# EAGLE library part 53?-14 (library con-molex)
CONNECTOR wire to board 1.25 mm (.049 inch) pitch header

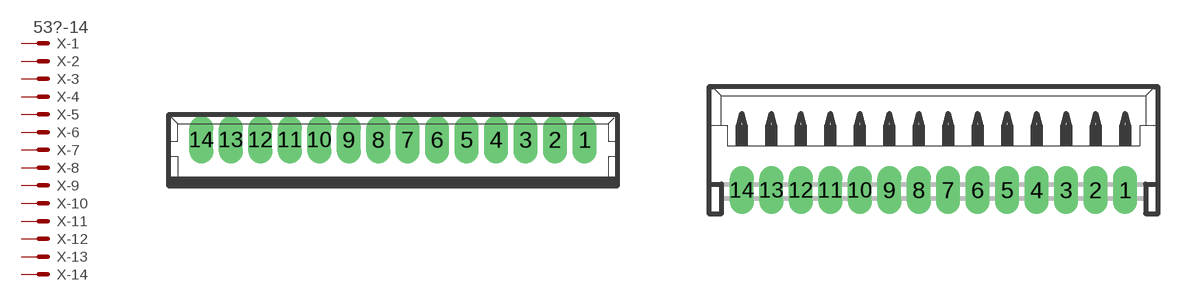
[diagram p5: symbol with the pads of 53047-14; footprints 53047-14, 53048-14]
Designator prefix X; gates -1=MV -2=M -3=M -4=M -5=M -6=M -7=M -8=M -9=M -10=M -11=M -12=M -13=M -14=M

## 53047-14 (MPN: 53047-1410; OC_FARNELL: 9732900; OC_NEWARK: 98K9830)  [53047-14]
1  -1:S  pas
2  -2:S  pas
3  -3:S  pas
4  -4:S  pas
5  -5:S  pas
6  -6:S  pas
7  -7:S  pas
8  -8:S  pas
9  -9:S  pas
10  -10:S  pas
11  -11:S  pas
12  -12:S  pas
13  -13:S  pas
14  -14:S  pas

## 53048-14 (MPN: 53048-1410; OC_FARNELL: 1012240; OC_NEWARK: 98K9839)  [53048-14]
Pads as for 53047-14

## 53261-14 (OC_FARNELL: 1125364; OC_NEWARK: unknown)  [53261-14]
Pads as for 53047-14

## 53398-14 (OC_FARNELL: 9786384; OC_NEWARK: unknown)  [53398-14]
Pads as for 53047-14

## Footprint 53047-14 (pad centres in mm)
CONNECTOR wire to board 1.25 mm (.049 inch) pitch header straight Sourcxe: http://www.molex.com/pdm_docs/sd/530470210_sd.pdf
drill 0.5 pad 0.698 long: 1 8.125,0.45; 2 6.875,0.45; 3 5.625,0.45; 4 4.375,0.45; 5 3.125,0.45; 6 1.875,0.45; 7 0.625,0.45; 8 -0.625,0.45; 9 -1.875,0.45; 10 -3.125,0.45; 11 -4.375,0.45; 12 -5.625,0.45; 13 -6.875,0.45; 14 -8.125,0.45

## Footprint 53048-14 (pad centres in mm)
CONNECTOR wire to board 1.25 mm (.049 inch) pitch header right angle
drill 0.5 pad 0.698 long: 1 8.125,-1.25; 2 6.875,-1.25; 3 5.625,-1.25; 4 4.375,-1.25; 5 3.125,-1.25; 6 1.875,-1.25; 7 0.625,-1.25; 8 -0.625,-1.25; 9 -1.875,-1.25; 10 -3.125,-1.25; 11 -4.375,-1.25; 12 -5.625,-1.25; 13 -6.875,-1.25; 14 -8.125,-1.25

## Footprint 53261-14 (pad centres in mm)
CONNECTOR wire to board 1.25 mm (.049 inch) pitch header SMT right angle
smd 0.8 x 2: 1 8.125,-2.5; 2 6.875,-2.5; 3 5.625,-2.5; 4 4.375,-2.5; 5 3.125,-2.5; 6 1.875,-2.5; 7 0.625,-2.5; 8 -0.625,-2.5; 9 -1.875,-2.5; 10 -3.125,-2.5; 11 -4.375,-2.5; 12 -5.625,-2.5; 13 -6.875,-2.5; 14 -8.125,-2.5
smd 2.1 x 3: S1 10.625,0.625; S2 -10.625,0.625

## Footprint 53398-14 (pad centres in mm)
CONNECTOR wire to board 1.25 mm (.049 inch) pitch header SMT straight
smd 0.8 x 1.8: 1 8.125,-2.5; 2 6.875,-2.5; 3 5.625,-2.5; 4 4.375,-2.5; 5 3.125,-2.5; 6 1.875,-2.5; 7 0.625,-2.5; 8 -0.625,-2.5; 9 -1.875,-2.5; 10 -3.125,-2.5; 11 -4.375,-2.5; 12 -5.625,-2.5; 13 -6.875,-2.5; 14 -8.125,-2.5
smd 2.1 x 3: S1 10.625,0.625; S2 -10.625,0.625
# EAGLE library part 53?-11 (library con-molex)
CONNECTOR wire to board 1.25 mm (.049 inch) pitch header

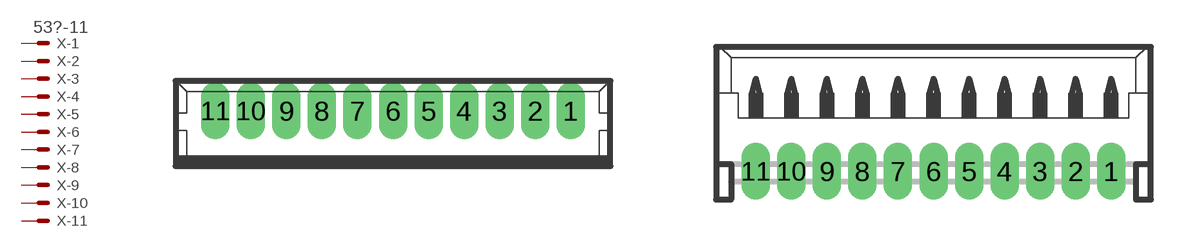
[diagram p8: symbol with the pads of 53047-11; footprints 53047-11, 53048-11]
Designator prefix X; gates -1=MV -2=M -3=M -4=M -5=M -6=M -7=M -8=M -9=M -10=M -11=M

## 53047-11 (MF: WALDOM/MOLEX; MPN: 53047-1110; OC_FARNELL: unknown; OC_NEWARK: 18M8168)  [53047-11]
1  -1:S  pas
2  -2:S  pas
3  -3:S  pas
4  -4:S  pas
5  -5:S  pas
6  -6:S  pas
7  -7:S  pas
8  -8:S  pas
9  -9:S  pas
10  -10:S  pas
11  -11:S  pas

## 53048-11 (MPN: 53048-1110; OC_FARNELL: unknown; OC_NEWARK: 28M9451)  [53048-11]
Pads as for 53047-11

## 53261-11 (MPN: 53261-1171; OC_FARNELL: 1756926; OC_NEWARK: 58K8238)  [53261-11]
Pads as for 53047-11

## 53398-11 (OC_FARNELL: 9786376; OC_NEWARK: unknown)  [53398-11]
Pads as for 53047-11

## Footprint 53047-11 (pad centres in mm)
CONNECTOR wire to board 1.25 mm (.049 inch) pitch header straight Sourcxe: http://www.molex.com/pdm_docs/sd/530470210_sd.pdf
drill 0.5 pad 0.698 long: 1 6.25,0.45; 2 5,0.45; 3 3.75,0.45; 4 2.5,0.45; 5 1.25,0.45; 6 0,0.45; 7 -1.25,0.45; 8 -2.5,0.45; 9 -3.75,0.45; 10 -5,0.45; 11 -6.25,0.45

## Footprint 53048-11 (pad centres in mm)
CONNECTOR wire to board 1.25 mm (.049 inch) pitch header right angle
drill 0.5 pad 0.698 long: 1 6.25,-1.25; 2 5,-1.25; 3 3.75,-1.25; 4 2.5,-1.25; 5 1.25,-1.25; 6 0,-1.25; 7 -1.25,-1.25; 8 -2.5,-1.25; 9 -3.75,-1.25; 10 -5,-1.25; 11 -6.25,-1.25

## Footprint 53261-11 (pad centres in mm)
CONNECTOR wire to board 1.25 mm (.049 inch) pitch header SMT right angle
smd 0.8 x 2: 1 6.25,-2.5; 2 5,-2.5; 3 3.75,-2.5; 4 2.5,-2.5; 5 1.25,-2.5; 6 0,-2.5; 7 -1.25,-2.5; 8 -2.5,-2.5; 9 -3.75,-2.5; 10 -5,-2.5; 11 -6.25,-2.5
smd 2.1 x 3: S1 8.75,0.625; S2 -8.75,0.625

## Footprint 53398-11 (pad centres in mm)
CONNECTOR wire to board 1.25 mm (.049 inch) pitch header SMT straight
smd 0.8 x 1.8: 1 6.25,-2.5; 2 5,-2.5; 3 3.75,-2.5; 4 2.5,-2.5; 5 1.25,-2.5; 6 0,-2.5; 7 -1.25,-2.5; 8 -2.5,-2.5; 9 -3.75,-2.5; 10 -5,-2.5; 11 -6.25,-2.5
smd 2.1 x 3: S1 8.75,0.625; S2 -8.75,0.625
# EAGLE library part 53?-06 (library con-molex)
CONNECTOR wire to board 1.25 mm (.049 inch) pitch header

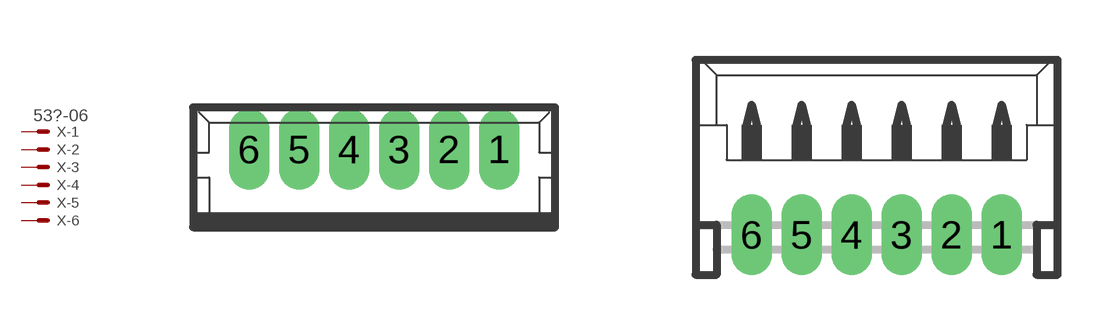
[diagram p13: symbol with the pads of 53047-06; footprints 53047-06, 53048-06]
Designator prefix X; gates -1=MV -2=M -3=M -4=M -5=M -6=M

## 53047-06 (MPN: 53047-0610-C; OC_FARNELL: 9733078; OC_NEWARK: 03M2965)  [53047-06]
1  -1:S  pas
2  -2:S  pas
3  -3:S  pas
4  -4:S  pas
5  -5:S  pas
6  -6:S  pas

## 53048-06 (MF: WALDOM/MOLEX; MPN: 53048-0610; OC_FARNELL: 1012260; OC_NEWARK: 38C9911)  [53048-06]
Pads as for 53047-06

## 53261-06 (OC_FARNELL: 1125375; OC_NEWARK: unknown)  [53261-06]
Pads as for 53047-06

## 53398-06 (OC_FARNELL: 1125368; OC_NEWARK: unknown)  [53398-06]
Pads as for 53047-06

## Footprint 53047-06 (pad centres in mm)
CONNECTOR wire to board 1.25 mm (.049 inch) pitch header straight Sourcxe: http://www.molex.com/pdm_docs/sd/530470210_sd.pdf
drill 0.5 pad 0.698 long: 1 3.125,0.45; 2 1.875,0.45; 3 0.625,0.45; 4 -0.625,0.45; 5 -1.875,0.45; 6 -3.125,0.45

## Footprint 53048-06 (pad centres in mm)
CONNECTOR wire to board 1.25 mm (.049 inch) pitch header right angle
drill 0.5 pad 0.698 long: 1 3.125,-1.25; 2 1.875,-1.25; 3 0.625,-1.25; 4 -0.625,-1.25; 5 -1.875,-1.25; 6 -3.125,-1.25

## Footprint 53261-06 (pad centres in mm)
CONNECTOR wire to board 1.25 mm (.049 inch) pitch header SMT right angle
smd 0.8 x 2: 1 3.125,-2.5; 2 1.875,-2.5; 3 0.625,-2.5; 4 -0.625,-2.5; 5 -1.875,-2.5; 6 -3.125,-2.5
smd 2.1 x 3: S1 5.625,0.625; S2 -5.625,0.625

## Footprint 53398-06 (pad centres in mm)
CONNECTOR wire to board 1.25 mm (.049 inch) pitch header SMT straight
smd 0.8 x 1.8: 1 3.125,-2.5; 2 1.875,-2.5; 3 0.625,-2.5; 4 -0.625,-2.5; 5 -1.875,-2.5; 6 -3.125,-2.5
smd 2.1 x 3: S1 5.625,0.625; S2 -5.625,0.625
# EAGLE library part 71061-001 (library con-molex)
CONNECTOR 50-pin 1.27mm (.050 inch) pitch SCSI+ unshielded receptacle right angle all plastic

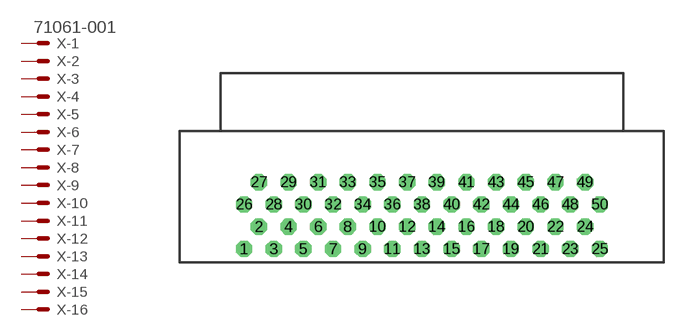
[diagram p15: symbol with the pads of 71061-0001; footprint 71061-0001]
Designator prefix X; gates -1=MV -2=M -3=M -4=M -5=M -6=M -7=M -8=M -9=M -10=M -11=M -12=M -13=M -14=M -15=M -16=M -17=M -18=M -19=M -20=M -21=M -22=M -23=M -24=M -25=M -26=M -27=M -28=M -29=M -30=M -31=M -32=M -33=M -34=M -35=M -36=M -37=M -38=M -39=M -40=M -41=M -42=M -43=M -44=M -45=M -46=M -47=M -48=M -49=M -50=M

## 71061-001 (OC_FARNELL: unknown; OC_NEWARK: unknown)  [71061-0001]
1  -1:S  pas
2  -2:S  pas
3  -3:S  pas
4  -4:S  pas
5  -5:S  pas
6  -6:S  pas
7  -7:S  pas
8  -8:S  pas
9  -9:S  pas
10  -10:S  pas
11  -11:S  pas
12  -12:S  pas
13  -13:S  pas
14  -14:S  pas
15  -15:S  pas
16  -16:S  pas
17  -17:S  pas
18  -18:S  pas
19  -19:S  pas
20  -20:S  pas
21  -21:S  pas
22  -22:S  pas
23  -23:S  pas
24  -24:S  pas
25  -25:S  pas
26  -26:S  pas
27  -27:S  pas
28  -28:S  pas
29  -29:S  pas
30  -30:S  pas
31  -31:S  pas
32  -32:S  pas
33  -33:S  pas
34  -34:S  pas
35  -35:S  pas
36  -36:S  pas
37  -37:S  pas
38  -38:S  pas
39  -39:S  pas
40  -40:S  pas
41  -41:S  pas
42  -42:S  pas
43  -43:S  pas
44  -44:S  pas
45  -45:S  pas
46  -46:S  pas
47  -47:S  pas
48  -48:S  pas
49  -49:S  pas
50  -50:S  pas

## Footprint 71061-0001 (pad centres in mm)
CONNECTOR 50-pin 1.27mm (.050 inch) pitch SCSI+ unshielded receptacle, right angle, all plastic Source: http://www.molex.com/product/io/71061.html
drill 0.813 pad 1.397 octagon: 1 -15.24,-5.73; 2 -13.97,-3.82; 3 -12.7,-5.73; 4 -11.43,-3.82; 5 -10.16,-5.73; 6 -8.89,-3.82; 7 -7.62,-5.73; 8 -6.35,-3.82; 9 -5.08,-5.73; 10 -3.81,-3.82; 11 -2.54,-5.73; 12 -1.27,-3.82; 13 0,-5.73; 14 1.27,-3.82; 15 2.54,-5.73; 16 3.81,-3.82; 17 5.08,-5.73; 18 6.35,-3.82; 19 7.62,-5.73; 20 8.89,-3.82; 21 10.16,-5.73; 22 11.43,-3.82; 23 12.7,-5.73; 24 13.97,-3.82; 25 15.24,-5.73; 26 -15.24,-1.91; 27 -13.97,0; 28 -12.7,-1.91; 29 -11.43,0; 30 -10.16,-1.91; 31 -8.89,0; 32 -7.62,-1.91; 33 -6.35,0; 34 -5.08,-1.91; 35 -3.81,0; 36 -2.54,-1.91; 37 -1.27,0; 38 0,-1.91; 39 1.27,0; 40 2.54,-1.91; 41 3.81,0; 42 5.08,-1.91; 43 6.35,0; 44 7.62,-1.91; 45 8.89,0; 46 10.16,-1.91; 47 11.43,0; 48 12.7,-1.91; 49 13.97,0; 50 15.24,-1.91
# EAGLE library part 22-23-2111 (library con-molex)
.100" (2.54mm) Center Header - 11 Pin

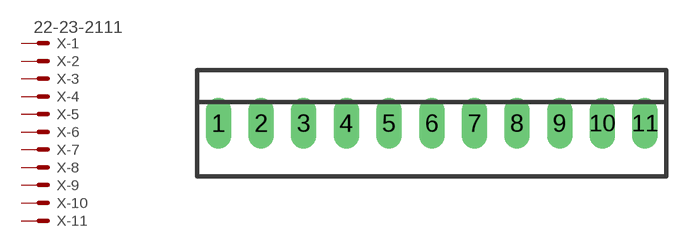
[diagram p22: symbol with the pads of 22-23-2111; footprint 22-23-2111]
Designator prefix X; gates -1=MV -2=M -3=M -4=M -5=M -6=M -7=M -8=M -9=M -10=M -11=M

## 22-23-2111 (MF: MOLEX; MPN: 22-23-2111; OC_FARNELL: 5388879; OC_NEWARK: 27C9916)  [22-23-2111]
1  -1:S  pas
2  -2:S  pas
3  -3:S  pas
4  -4:S  pas
5  -5:S  pas
6  -6:S  pas
7  -7:S  pas
8  -8:S  pas
9  -9:S  pas
10  -10:S  pas
11  -11:S  pas

## Footprint 22-23-2111 (pad centres in mm)
.100" (2.54mm) Center Header - 11 Pin
drill 1 long: 1 -12.7,0; 2 -10.16,0; 3 -7.62,0; 4 -5.08,0; 5 -2.54,0; 6 0,0; 7 2.54,0; 8 5.08,0; 9 7.62,0; 10 10.16,0; 11 12.7,0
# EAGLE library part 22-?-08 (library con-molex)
CONNECTOR wire to board 2.54 mm (.1 inch) pitch header

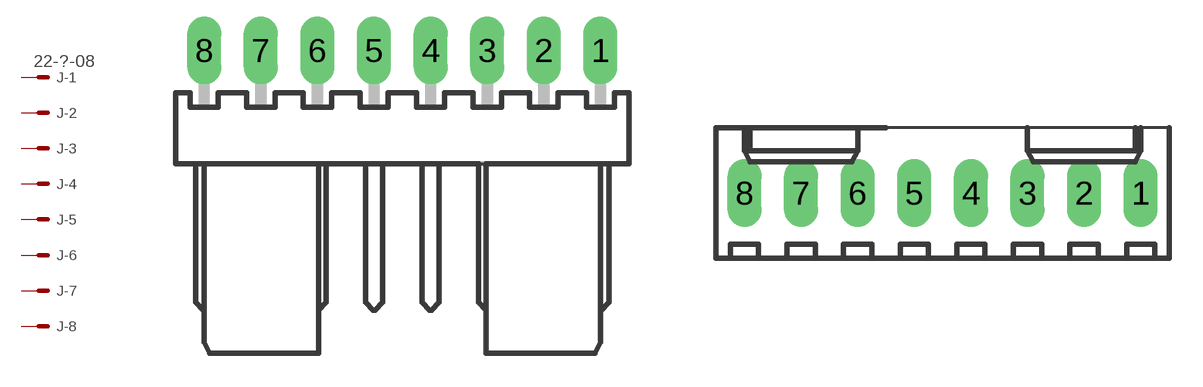
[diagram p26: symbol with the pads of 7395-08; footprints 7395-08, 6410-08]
Designator prefix J; gates -1=MV -2=M -3=M -4=M -5=M -6=M -7=M -8=M

## 22-05-7088-08 (OC_FARNELL: unknown; OC_NEWARK: unknown)  [7395-08]
1  -1:S  pas
2  -2:S  pas
3  -3:S  pas
4  -4:S  pas
5  -5:S  pas
6  -6:S  pas
7  -7:S  pas
8  -8:S  pas

## 22-27-2081-08 (OC_FARNELL: unknown; OC_NEWARK: unknown)  [6410-08]
Pads as for 7395-08

## Footprint 7395-08 (pad centres in mm)
MOLEX 2.54mm KK RA CONNECTOR Fixed Orientation
drill 1.016 long: 1 8.89,0; 2 6.35,0; 3 3.81,0; 4 1.27,0; 5 -1.27,0; 6 -3.81,0; 7 -6.35,0; 8 -8.89,0

## Footprint 6410-08 (pad centres in mm)
MOLEX 2.54mm KK CONNECTOR
drill 1.016 long: 1 8.89,0; 2 6.35,0; 3 3.81,0; 4 1.27,0; 5 -1.27,0; 6 -3.81,0; 7 -6.35,0; 8 -8.89,0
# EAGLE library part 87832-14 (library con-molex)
Milli-Grid Header 2.00mm (.079") Pitch

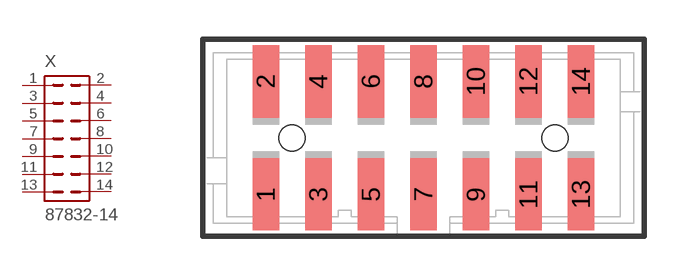
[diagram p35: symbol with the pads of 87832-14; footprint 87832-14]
Designator prefix X

## 87832-14 (OC_FARNELL: 7434698; OC_NEWARK: unknown)  [87832-14]
1  1  pas
2  2  pas
3  3  pas
4  4  pas
5  5  pas
6  6  pas
7  7  pas
8  8  pas
9  9  pas
10  10  pas
11  11  pas
12  12  pas
13  13  pas
14  14  pas

## Footprint 87832-14 (pad centres in mm)
PCB Headers 2.00mm (.079") Pitch Milli-Grid Header, Vertical, Shrouded
smd 1 x 2.75: 1 -6,-2.15; 2 -6,2.15; 3 -4,-2.15; 4 -4,2.15; 5 -2,-2.15; 6 -2,2.15; 7 0,-2.15; 8 0,2.15; 9 2,-2.15; 10 2,2.15; 11 4,-2.15; 12 4,2.15; 13 6,-2.15; 14 6,2.15
hole 1 at -5,0
hole 1 at 5,0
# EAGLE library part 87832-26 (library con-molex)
Milli-Grid Header 2.00mm (.079") Pitch

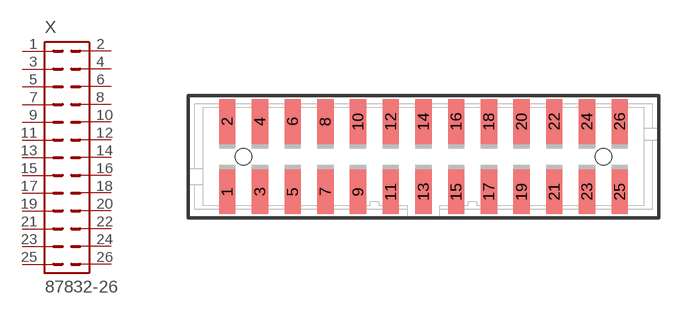
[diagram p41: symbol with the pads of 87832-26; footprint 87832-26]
Designator prefix X

## 87832-26 (OC_FARNELL: 1550428; OC_NEWARK: unknown)  [87832-26]
1  1  pas
2  2  pas
3  3  pas
4  4  pas
5  5  pas
6  6  pas
7  7  pas
8  8  pas
9  9  pas
10  10  pas
11  11  pas
12  12  pas
13  13  pas
14  14  pas
15  15  pas
16  16  pas
17  17  pas
18  18  pas
19  19  pas
20  20  pas
21  21  pas
22  22  pas
23  23  pas
24  24  pas
25  25  pas
26  26  pas

## Footprint 87832-26 (pad centres in mm)
PCB Headers 2.00mm (.079") Pitch Milli-Grid Header, Vertical, Shrouded
smd 1 x 2.75: 1 -12,-2.15; 2 -12,2.15; 3 -10,-2.15; 4 -10,2.15; 5 -8,-2.15; 6 -8,2.15; 7 -6,-2.15; 8 -6,2.15; 9 -4,-2.15; 10 -4,2.15; 11 -2,-2.15; 12 -2,2.15; 13 0,-2.15; 14 0,2.15; 15 2,-2.15; 16 2,2.15; 17 4,-2.15; 18 4,2.15; 19 6,-2.15; 20 6,2.15; 21 8,-2.15; 22 8,2.15; 23 10,-2.15; 24 10,2.15; 25 12,-2.15; 26 12,2.15
hole 1 at -11,0
hole 1 at 11,0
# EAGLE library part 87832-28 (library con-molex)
Milli-Grid Header 2.00mm (.079") Pitch

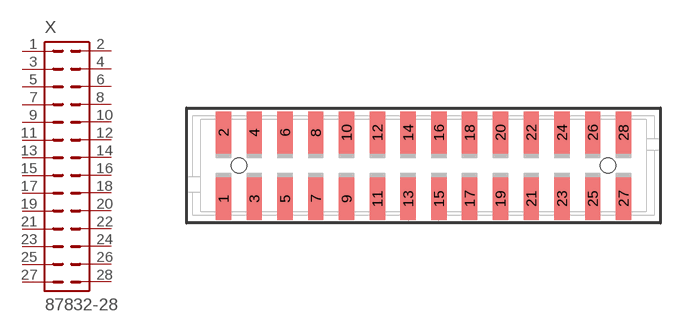
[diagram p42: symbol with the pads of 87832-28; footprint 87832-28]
Designator prefix X

## 87832-28 (MPN: 87832-2821; OC_FARNELL: unknown; OC_NEWARK: 94M1941)  [87832-28]
1  1  pas
2  2  pas
3  3  pas
4  4  pas
5  5  pas
6  6  pas
7  7  pas
8  8  pas
9  9  pas
10  10  pas
11  11  pas
12  12  pas
13  13  pas
14  14  pas
15  15  pas
16  16  pas
17  17  pas
18  18  pas
19  19  pas
20  20  pas
21  21  pas
22  22  pas
23  23  pas
24  24  pas
25  25  pas
26  26  pas
27  27  pas
28  28  pas

## Footprint 87832-28 (pad centres in mm)
PCB Headers 2.00mm (.079") Pitch Milli-Grid Header, Vertical, Shrouded
smd 1 x 2.75: 1 -13,-2.15; 2 -13,2.15; 3 -11,-2.15; 4 -11,2.15; 5 -9,-2.15; 6 -9,2.15; 7 -7,-2.15; 8 -7,2.15; 9 -5,-2.15; 10 -5,2.15; 11 -3,-2.15; 12 -3,2.15; 13 -1,-2.15; 14 -1,2.15; 15 1,-2.15; 16 1,2.15; 17 3,-2.15; 18 3,2.15; 19 5,-2.15; 20 5,2.15; 21 7,-2.15; 22 7,2.15; 23 9,-2.15; 24 9,2.15; 25 11,-2.15; 26 11,2.15; 27 13,-2.15; 28 13,2.15
hole 1 at -12,0
hole 1 at 12,0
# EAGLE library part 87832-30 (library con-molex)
Milli-Grid Header 2.00mm (.079") Pitch

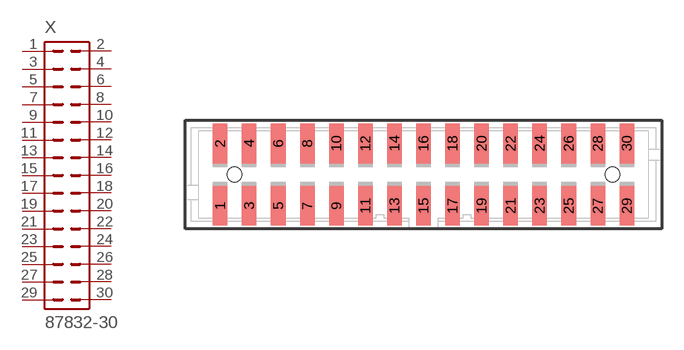
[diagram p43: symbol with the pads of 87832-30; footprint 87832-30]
Designator prefix X

## 87832-30 (OC_FARNELL: unknown; OC_NEWARK: unknown)  [87832-30]
1  1  pas
2  2  pas
3  3  pas
4  4  pas
5  5  pas
6  6  pas
7  7  pas
8  8  pas
9  9  pas
10  10  pas
11  11  pas
12  12  pas
13  13  pas
14  14  pas
15  15  pas
16  16  pas
17  17  pas
18  18  pas
19  19  pas
20  20  pas
21  21  pas
22  22  pas
23  23  pas
24  24  pas
25  25  pas
26  26  pas
27  27  pas
28  28  pas
29  29  pas
30  30  pas

## Footprint 87832-30 (pad centres in mm)
PCB Headers 2.00mm (.079") Pitch Milli-Grid Header, Vertical, Shrouded
smd 1 x 2.75: 1 -14,-2.15; 2 -14,2.15; 3 -12,-2.15; 4 -12,2.15; 5 -10,-2.15; 6 -10,2.15; 7 -8,-2.15; 8 -8,2.15; 9 -6,-2.15; 10 -6,2.15; 11 -4,-2.15; 12 -4,2.15; 13 -2,-2.15; 14 -2,2.15; 15 0,-2.15; 16 0,2.15; 17 2,-2.15; 18 2,2.15; 19 4,-2.15; 20 4,2.15; 21 6,-2.15; 22 6,2.15; 23 8,-2.15; 24 8,2.15; 25 10,-2.15; 26 10,2.15; 27 12,-2.15; 28 12,2.15; 29 14,-2.15; 30 14,2.15
hole 1 at -13,0
hole 1 at 13,0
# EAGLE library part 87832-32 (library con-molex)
Milli-Grid Header 2.00mm (.079") Pitch

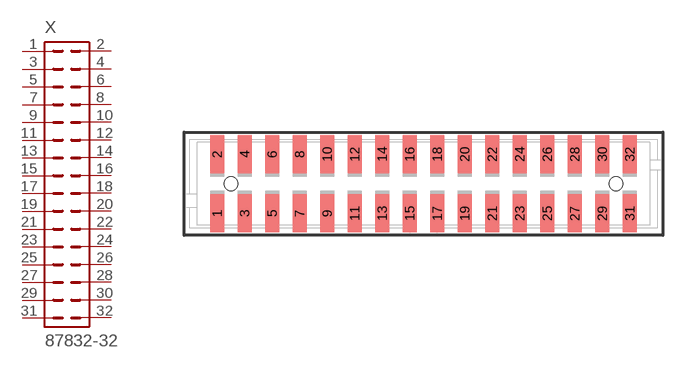
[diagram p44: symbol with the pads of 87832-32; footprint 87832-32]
Designator prefix X

## 87832-32 (OC_FARNELL: unknown; OC_NEWARK: unknown)  [87832-32]
1  1  pas
2  2  pas
3  3  pas
4  4  pas
5  5  pas
6  6  pas
7  7  pas
8  8  pas
9  9  pas
10  10  pas
11  11  pas
12  12  pas
13  13  pas
14  14  pas
15  15  pas
16  16  pas
17  17  pas
18  18  pas
19  19  pas
20  20  pas
21  21  pas
22  22  pas
23  23  pas
24  24  pas
25  25  pas
26  26  pas
27  27  pas
28  28  pas
29  29  pas
30  30  pas
31  31  pas
32  32  pas

## Footprint 87832-32 (pad centres in mm)
PCB Headers 2.00mm (.079") Pitch Milli-Grid Header, Vertical, Shrouded
smd 1 x 2.75: 1 -15,-2.15; 2 -15,2.15; 3 -13,-2.15; 4 -13,2.15; 5 -11,-2.15; 6 -11,2.15; 7 -9,-2.15; 8 -9,2.15; 9 -7,-2.15; 10 -7,2.15; 11 -5,-2.15; 12 -5,2.15; 13 -3,-2.15; 14 -3,2.15; 15 -1,-2.15; 16 -1,2.15; 17 1,-2.15; 18 1,2.15; 19 3,-2.15; 20 3,2.15; 21 5,-2.15; 22 5,2.15; 23 7,-2.15; 24 7,2.15; 25 9,-2.15; 26 9,2.15; 27 11,-2.15; 28 11,2.15; 29 13,-2.15; 30 13,2.15; 31 15,-2.15; 32 15,2.15
hole 1 at -14,0
hole 1 at 14,0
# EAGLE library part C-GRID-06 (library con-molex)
CONNECTOR wire to board 2.54 mm (0.100") pitch header

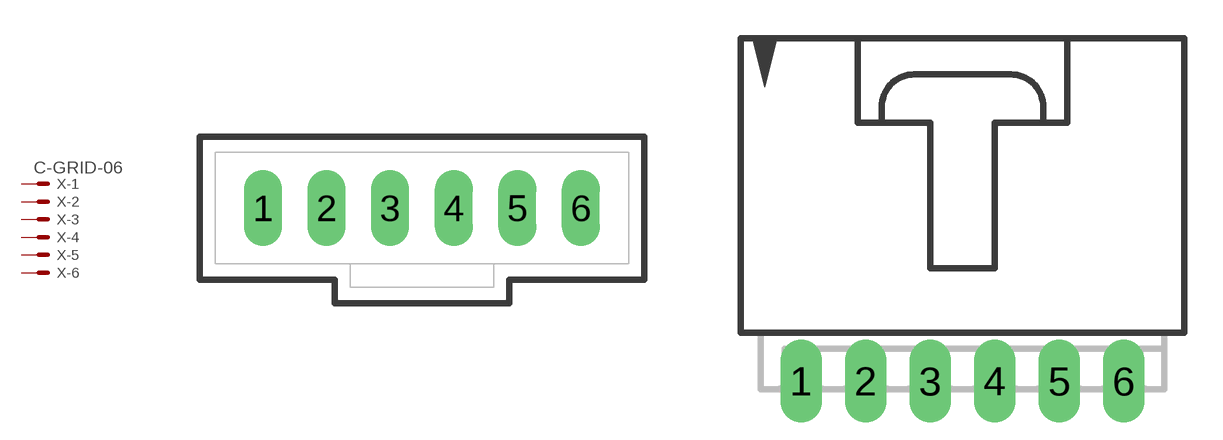
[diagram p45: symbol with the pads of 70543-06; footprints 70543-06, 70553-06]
Designator prefix X; gates -1=MV -2=M -3=M -4=M -5=M -6=M

## C-GRID-06-70543 (OC_FARNELL: unknown; OC_NEWARK: unknown)  [70543-06]
1  -1:S  pas
2  -2:S  pas
3  -3:S  pas
4  -4:S  pas
5  -5:S  pas
6  -6:S  pas

## C-GRID-06-70553 (OC_FARNELL: unknown; OC_NEWARK: unknown)  [70553-06]
Pads as for 70543-06

## C-GRID-06-74099 (OC_FARNELL: unknown; OC_NEWARK: unknown)  [74099-06]
Pads as for 70543-06

## C-GRID-06-15-91 (OC_FARNELL: unknown; OC_NEWARK: unknown)  [15-91-06]
Pads as for 70543-06

## Footprint 70543-06 (pad centres in mm)
C-Grid SL Connector vertical, 6 pin
drill 1.016 long: 1 -6.35,0; 2 -3.81,0; 3 -1.27,0; 4 1.27,0; 5 3.81,0; 6 6.35,0

## Footprint 70553-06 (pad centres in mm)
C-Grid SL Connector right angle, 6 pin
drill 1.092 long: 1 -6.35,-7.62; 2 -3.81,-7.62; 3 -1.27,-7.62; 4 1.27,-7.62; 5 3.81,-7.62; 6 6.35,-7.62

## Footprint 74099-06 (pad centres in mm)
C-Grid SL Connector vertical SMD, 6 pin
smd 1.27 x 3.175: 1 -6.35,-2.223; 2 -3.81,2.223; 3 -1.27,-2.223; 4 1.27,2.223; 5 3.81,-2.223; 6 6.35,2.223

## Footprint 15-91-06 (pad centres in mm)
C-Grid SL Connector right angle SMD, 6 pin
smd 1.651 x 5.334: 1 -6.35,-10.795; 2 -3.81,-10.795; 3 -1.27,-10.795; 4 1.27,-10.795; 5 3.81,-10.795; 6 6.35,-10.795
hole 3.404 at -7.747,0.838
hole 3.404 at 7.747,0.838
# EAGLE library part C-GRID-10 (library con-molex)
CONNECTOR wire to board 2.54 mm (0.100") pitch header

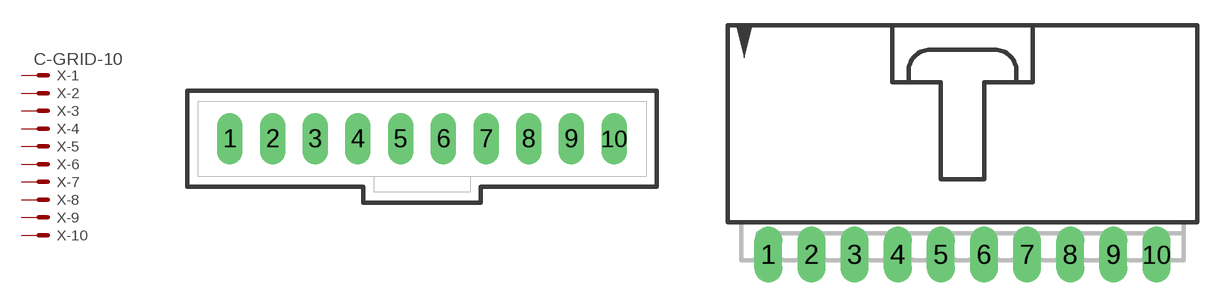
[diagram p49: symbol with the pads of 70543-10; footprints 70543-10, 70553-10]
Designator prefix X; gates -1=MV -2=M -3=M -4=M -5=M -6=M -7=M -8=M -9=M -10=M

## C-GRID-10-70543 (OC_FARNELL: unknown; OC_NEWARK: unknown)  [70543-10]
1  -1:S  pas
2  -2:S  pas
3  -3:S  pas
4  -4:S  pas
5  -5:S  pas
6  -6:S  pas
7  -7:S  pas
8  -8:S  pas
9  -9:S  pas
10  -10:S  pas

## C-GRID-10-70553 (OC_FARNELL: unknown; OC_NEWARK: unknown)  [70553-10]
Pads as for 70543-10

## C-GRID-10-74099 (OC_FARNELL: unknown; OC_NEWARK: unknown)  [74099-10]
Pads as for 70543-10

## C-GRID-10-15-91 (OC_FARNELL: unknown; OC_NEWARK: unknown)  [15-91-10]
Pads as for 70543-10

## Footprint 70543-10 (pad centres in mm)
C-Grid SL Connector vertical, 10 pin
drill 1.016 long: 1 -11.43,0; 2 -8.89,0; 3 -6.35,0; 4 -3.81,0; 5 -1.27,0; 6 1.27,0; 7 3.81,0; 8 6.35,0; 9 8.89,0; 10 11.43,0

## Footprint 70553-10 (pad centres in mm)
C-Grid SL Connector right angle, 10 pin
drill 1.092 long: 1 -11.43,-7.62; 2 -8.89,-7.62; 3 -6.35,-7.62; 4 -3.81,-7.62; 5 -1.27,-7.62; 6 1.27,-7.62; 7 3.81,-7.62; 8 6.35,-7.62; 9 8.89,-7.62; 10 11.43,-7.62

## Footprint 74099-10 (pad centres in mm)
C-Grid SL Connector vertical SMD, 10 pin
smd 1.27 x 3.175: 1 -11.43,-2.223; 2 -8.89,2.223; 3 -6.35,-2.223; 4 -3.81,2.223; 5 -1.27,-2.223; 6 1.27,2.223; 7 3.81,-2.223; 8 6.35,2.223; 9 8.89,-2.223; 10 11.43,2.223

## Footprint 15-91-10 (pad centres in mm)
C-Grid SL Connector right angle SMD, 10 pin
smd 1.651 x 5.334: 1 -11.43,-10.795; 2 -8.89,-10.795; 3 -6.35,-10.795; 4 -3.81,-10.795; 5 -1.27,-10.795; 6 1.27,-10.795; 7 3.81,-10.795; 8 6.35,-10.795; 9 8.89,-10.795; 10 11.43,-10.795
hole 3.404 at -12.827,0.838
hole 3.404 at 12.827,0.838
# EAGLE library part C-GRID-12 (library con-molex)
CONNECTOR wire to board 2.54 mm (0.100") pitch header

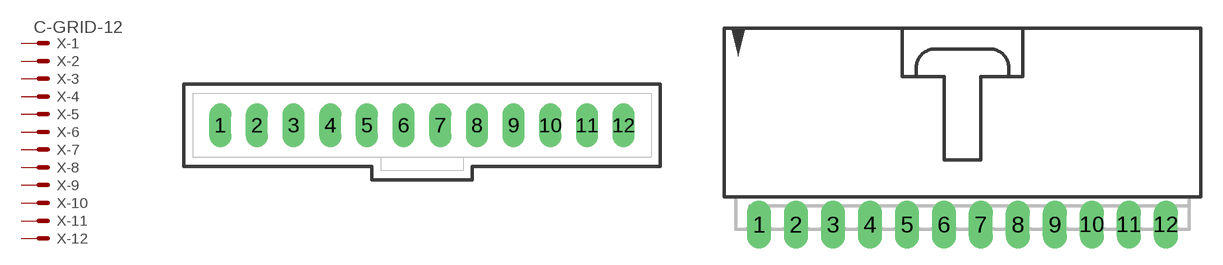
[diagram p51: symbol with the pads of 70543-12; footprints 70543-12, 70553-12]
Designator prefix X; gates -1=MV -2=M -3=M -4=M -5=M -6=M -7=M -8=M -9=M -10=M -11=M -12=M

## C-GRID-12-70543 (OC_FARNELL: unknown; OC_NEWARK: unknown)  [70543-12]
1  -1:S  pas
2  -2:S  pas
3  -3:S  pas
4  -4:S  pas
5  -5:S  pas
6  -6:S  pas
7  -7:S  pas
8  -8:S  pas
9  -9:S  pas
10  -10:S  pas
11  -11:S  pas
12  -12:S  pas

## C-GRID-12-70553 (OC_FARNELL: unknown; OC_NEWARK: unknown)  [70553-12]
Pads as for 70543-12

## C-GRID-12-74099 (OC_FARNELL: unknown; OC_NEWARK: unknown)  [74099-12]
Pads as for 70543-12

## C-GRID-12-15-91 (OC_FARNELL: unknown; OC_NEWARK: unknown)  [15-91-12]
Pads as for 70543-12

## Footprint 70543-12 (pad centres in mm)
C-Grid SL Connector vertical, 12 pin
drill 1.016 long: 1 -13.97,0; 2 -11.43,0; 3 -8.89,0; 4 -6.35,0; 5 -3.81,0; 6 -1.27,0; 7 1.27,0; 8 3.81,0; 9 6.35,0; 10 8.89,0; 11 11.43,0; 12 13.97,0

## Footprint 70553-12 (pad centres in mm)
C-Grid SL Connector right angle, 12 pin
drill 1.092 long: 1 -13.97,-7.62; 2 -11.43,-7.62; 3 -8.89,-7.62; 4 -6.35,-7.62; 5 -3.81,-7.62; 6 -1.27,-7.62; 7 1.27,-7.62; 8 3.81,-7.62; 9 6.35,-7.62; 10 8.89,-7.62; 11 11.43,-7.62; 12 13.97,-7.62

## Footprint 74099-12 (pad centres in mm)
C-Grid SL Connector vertical SMD, 12 pin
smd 1.27 x 3.175: 1 -13.97,-2.223; 2 -11.43,2.223; 3 -8.89,-2.223; 4 -6.35,2.223; 5 -3.81,-2.223; 6 -1.27,2.223; 7 1.27,-2.223; 8 3.81,2.223; 9 6.35,-2.223; 10 8.89,2.223; 11 11.43,-2.223; 12 13.97,2.223

## Footprint 15-91-12 (pad centres in mm)
C-Grid SL Connector right angle SMD, 12 pin
smd 1.651 x 5.334: 1 -13.97,-10.795; 2 -11.43,-10.795; 3 -8.89,-10.795; 4 -6.35,-10.795; 5 -3.81,-10.795; 6 -1.27,-10.795; 7 1.27,-10.795; 8 3.81,-10.795; 9 6.35,-10.795; 10 8.89,-10.795; 11 11.43,-10.795; 12 13.97,-10.795
hole 3.404 at -15.367,0.838
hole 3.404 at 15.367,0.838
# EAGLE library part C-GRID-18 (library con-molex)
CONNECTOR wire to board 2.54 mm (0.100") pitch header

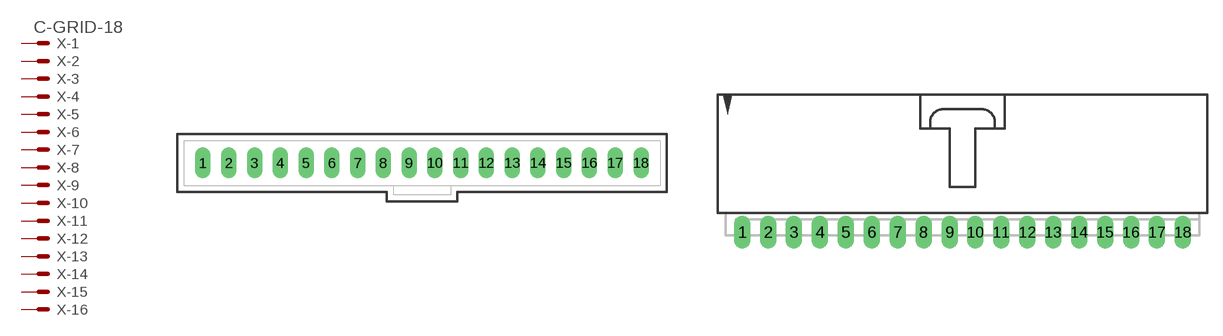
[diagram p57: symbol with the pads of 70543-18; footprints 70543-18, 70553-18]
Designator prefix X; gates -1=MV -2=M -3=M -4=M -5=M -6=M -7=M -8=M -9=M -10=M -11=M -12=M -13=M -14=M -15=M -16=M -17=M -18=M

## C-GRID-18-70543 (OC_FARNELL: unknown; OC_NEWARK: unknown)  [70543-18]
1  -1:S  pas
2  -2:S  pas
3  -3:S  pas
4  -4:S  pas
5  -5:S  pas
6  -6:S  pas
7  -7:S  pas
8  -8:S  pas
9  -9:S  pas
10  -10:S  pas
11  -11:S  pas
12  -12:S  pas
13  -13:S  pas
14  -14:S  pas
15  -15:S  pas
16  -16:S  pas
17  -17:S  pas
18  -18:S  pas

## C-GRID-18-70553 (OC_FARNELL: unknown; OC_NEWARK: unknown)  [70553-18]
Pads as for 70543-18

## Footprint 70543-18 (pad centres in mm)
C-Grid SL Connector vertical, 18 pin
drill 1.016 long: 1 -21.59,0; 2 -19.05,0; 3 -16.51,0; 4 -13.97,0; 5 -11.43,0; 6 -8.89,0; 7 -6.35,0; 8 -3.81,0; 9 -1.27,0; 10 1.27,0; 11 3.81,0; 12 6.35,0; 13 8.89,0; 14 11.43,0; 15 13.97,0; 16 16.51,0; 17 19.05,0; 18 21.59,0

## Footprint 70553-18 (pad centres in mm)
C-Grid SL Connector right angle, 18 pin
drill 1.092 long: 1 -21.59,-7.62; 2 -19.05,-7.62; 3 -16.51,-7.62; 4 -13.97,-7.62; 5 -11.43,-7.62; 6 -8.89,-7.62; 7 -6.35,-7.62; 8 -3.81,-7.62; 9 -1.27,-7.62; 10 1.27,-7.62; 11 3.81,-7.62; 12 6.35,-7.62; 13 8.89,-7.62; 14 11.43,-7.62; 15 13.97,-7.62; 16 16.51,-7.62; 17 19.05,-7.62; 18 21.59,-7.62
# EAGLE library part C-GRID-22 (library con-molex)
CONNECTOR wire to board 2.54 mm (0.100") pitch header

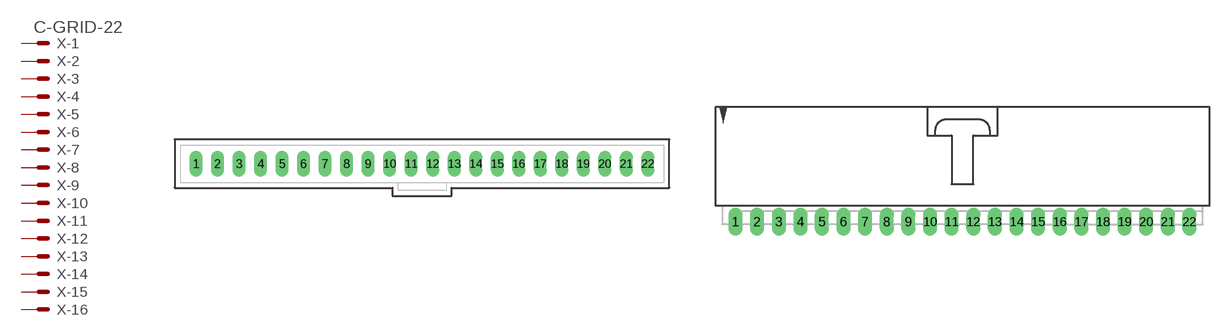
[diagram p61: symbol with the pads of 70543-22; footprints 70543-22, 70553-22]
Designator prefix X; gates -1=MV -2=M -3=M -4=M -5=M -6=M -7=M -8=M -9=M -10=M -11=M -12=M -13=M -14=M -15=M -16=M -17=M -18=M -19=M -20=M -21=M -22=M

## C-GRID-22-70543 (OC_FARNELL: unknown; OC_NEWARK: unknown)  [70543-22]
1  -1:S  pas
2  -2:S  pas
3  -3:S  pas
4  -4:S  pas
5  -5:S  pas
6  -6:S  pas
7  -7:S  pas
8  -8:S  pas
9  -9:S  pas
10  -10:S  pas
11  -11:S  pas
12  -12:S  pas
13  -13:S  pas
14  -14:S  pas
15  -15:S  pas
16  -16:S  pas
17  -17:S  pas
18  -18:S  pas
19  -19:S  pas
20  -20:S  pas
21  -21:S  pas
22  -22:S  pas

## C-GRID-22-70553 (OC_FARNELL: unknown; OC_NEWARK: unknown)  [70553-22]
Pads as for 70543-22

## Footprint 70543-22 (pad centres in mm)
C-Grid SL Connector vertical, 22 pin
drill 1.016 long: 1 -26.67,0; 2 -24.13,0; 3 -21.59,0; 4 -19.05,0; 5 -16.51,0; 6 -13.97,0; 7 -11.43,0; 8 -8.89,0; 9 -6.35,0; 10 -3.81,0; 11 -1.27,0; 12 1.27,0; 13 3.81,0; 14 6.35,0; 15 8.89,0; 16 11.43,0; 17 13.97,0; 18 16.51,0; 19 19.05,0; 20 21.59,0; 21 24.13,0; 22 26.67,0

## Footprint 70553-22 (pad centres in mm)
C-Grid SL Connector right angle, 22 pin
drill 1.092 long: 1 -26.67,-7.62; 2 -24.13,-7.62; 3 -21.59,-7.62; 4 -19.05,-7.62; 5 -16.51,-7.62; 6 -13.97,-7.62; 7 -11.43,-7.62; 8 -8.89,-7.62; 9 -6.35,-7.62; 10 -3.81,-7.62; 11 -1.27,-7.62; 12 1.27,-7.62; 13 3.81,-7.62; 14 6.35,-7.62; 15 8.89,-7.62; 16 11.43,-7.62; 17 13.97,-7.62; 18 16.51,-7.62; 19 19.05,-7.62; 20 21.59,-7.62; 21 24.13,-7.62; 22 26.67,-7.62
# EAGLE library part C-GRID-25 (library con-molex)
CONNECTOR wire to board 2.54 mm (0.100") pitch header

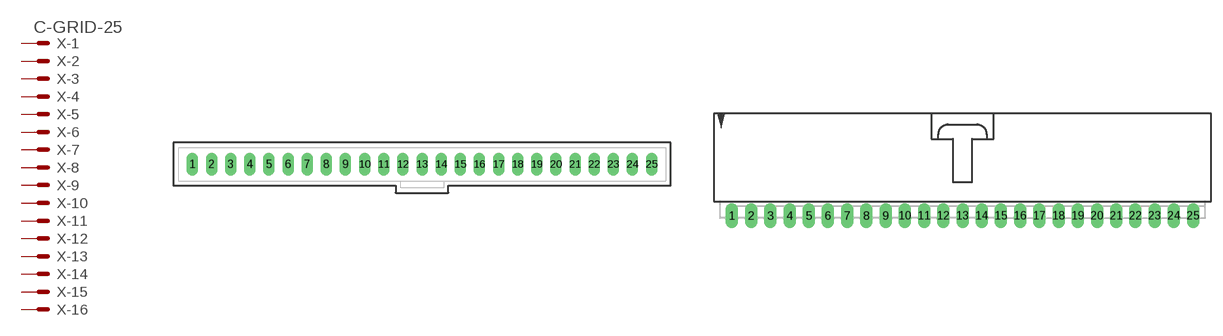
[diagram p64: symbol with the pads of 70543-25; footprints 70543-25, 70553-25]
Designator prefix X; gates -1=MV -2=M -3=M -4=M -5=M -6=M -7=M -8=M -9=M -10=M -11=M -12=M -13=M -14=M -15=M -16=M -17=M -18=M -19=M -20=M -21=M -22=M -23=M -24=M -25=M

## C-GRID-25-70543 (OC_FARNELL: unknown; OC_NEWARK: unknown)  [70543-25]
1  -1:S  pas
2  -2:S  pas
3  -3:S  pas
4  -4:S  pas
5  -5:S  pas
6  -6:S  pas
7  -7:S  pas
8  -8:S  pas
9  -9:S  pas
10  -10:S  pas
11  -11:S  pas
12  -12:S  pas
13  -13:S  pas
14  -14:S  pas
15  -15:S  pas
16  -16:S  pas
17  -17:S  pas
18  -18:S  pas
19  -19:S  pas
20  -20:S  pas
21  -21:S  pas
22  -22:S  pas
23  -23:S  pas
24  -24:S  pas
25  -25:S  pas

## C-GRID-25-70553 (OC_FARNELL: unknown; OC_NEWARK: unknown)  [70553-25]
Pads as for 70543-25

## Footprint 70543-25 (pad centres in mm)
C-Grid SL Connector vertical, 25 pin
drill 1.016 long: 1 -30.48,0; 2 -27.94,0; 3 -25.4,0; 4 -22.86,0; 5 -20.32,0; 6 -17.78,0; 7 -15.24,0; 8 -12.7,0; 9 -10.16,0; 10 -7.62,0; 11 -5.08,0; 12 -2.54,0; 13 0,0; 14 2.54,0; 15 5.08,0; 16 7.62,0; 17 10.16,0; 18 12.7,0; 19 15.24,0; 20 17.78,0; 21 20.32,0; 22 22.86,0; 23 25.4,0; 24 27.94,0; 25 30.48,0

## Footprint 70553-25 (pad centres in mm)
C-Grid SL Connector right angle, 25 pin
drill 1.092 long: 1 -30.48,-7.62; 2 -27.94,-7.62; 3 -25.4,-7.62; 4 -22.86,-7.62; 5 -20.32,-7.62; 6 -17.78,-7.62; 7 -15.24,-7.62; 8 -12.7,-7.62; 9 -10.16,-7.62; 10 -7.62,-7.62; 11 -5.08,-7.62; 12 -2.54,-7.62; 13 0,-7.62; 14 2.54,-7.62; 15 5.08,-7.62; 16 7.62,-7.62; 17 10.16,-7.62; 18 12.7,-7.62; 19 15.24,-7.62; 20 17.78,-7.62; 21 20.32,-7.62; 22 22.86,-7.62; 23 25.4,-7.62; 24 27.94,-7.62; 25 30.48,-7.62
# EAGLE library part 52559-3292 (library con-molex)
FFC/FPC-to-Board 0.50mm (.020") SMT, Vertical, ZIF Receptacle Source: http://www.molex.com/product/ffc/52559.html

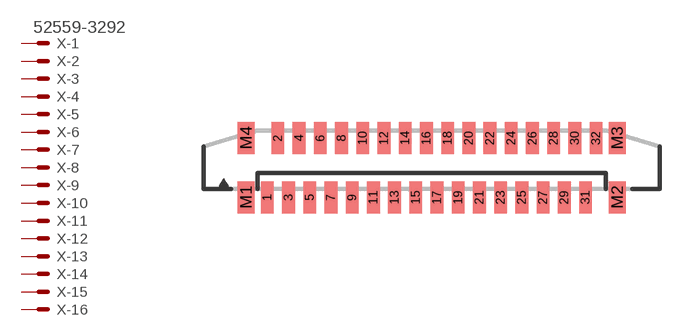
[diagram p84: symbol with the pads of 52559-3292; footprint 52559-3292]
Designator prefix X; gates -1=MV -2=M -3=M -4=M -5=M -6=M -7=M -8=M -9=M -10=M -11=M -12=M -13=M -14=M -15=M -16=M -17=M -18=M -19=M -20=M -21=M -22=M -23=M -24=M -25=M -26=M -27=M -28=M -29=M -30=M -31=M -32=M

## 52559-3292 (OC_FARNELL: unknown; OC_NEWARK: unknown)  [52559-3292]
1  -1:S  pas
2  -2:S  pas
3  -3:S  pas
4  -4:S  pas
5  -5:S  pas
6  -6:S  pas
7  -7:S  pas
8  -8:S  pas
9  -9:S  pas
10  -10:S  pas
11  -11:S  pas
12  -12:S  pas
13  -13:S  pas
14  -14:S  pas
15  -15:S  pas
16  -16:S  pas
17  -17:S  pas
18  -18:S  pas
19  -19:S  pas
20  -20:S  pas
21  -21:S  pas
22  -22:S  pas
23  -23:S  pas
24  -24:S  pas
25  -25:S  pas
26  -26:S  pas
27  -27:S  pas
28  -28:S  pas
29  -29:S  pas
30  -30:S  pas
31  -31:S  pas
32  -32:S  pas

## Footprint 52559-3292 (pad centres in mm)
FFC/FPC-to-Board 0.50mm (.020") SMT, Vertical, ZIF Receptacle Source: http://www.molex.com/product/ffc/52559.html
smd 0.6 x 1.5: 1 -7.75,-1.4; 2 -7.25,1.4; 3 -6.75,-1.4; 4 -6.25,1.4; 5 -5.75,-1.4; 6 -5.25,1.4; 7 -4.75,-1.4; 8 -4.25,1.4; 9 -3.75,-1.4; 10 -3.25,1.4; 11 -2.75,-1.4; 12 -2.25,1.4; 13 -1.75,-1.4; 14 -1.25,1.4; 15 -0.75,-1.4; 16 -0.25,1.4; 17 0.25,-1.4; 18 0.75,1.4; 19 1.25,-1.4; 20 1.75,1.4; 21 2.25,-1.4; 22 2.75,1.4; 23 3.25,-1.4; 24 3.75,1.4; 25 4.25,-1.4; 26 4.75,1.4; 27 5.25,-1.4; 28 5.75,1.4; 29 6.25,-1.4; 30 6.75,1.4; 31 7.25,-1.4; 32 7.75,1.4
smd 0.8 x 1.5: M1 -8.75,-1.4; M2 8.75,-1.4; M3 8.75,1.4; M4 -8.75,1.4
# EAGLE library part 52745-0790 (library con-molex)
FFC/FPC-to-Board 0.50mm (.020") SMT Top Contact Right Angle, ZIF, Style Receptacle 52745 / 52435 Source: http://www.molex.com/product/ffc/52745.html

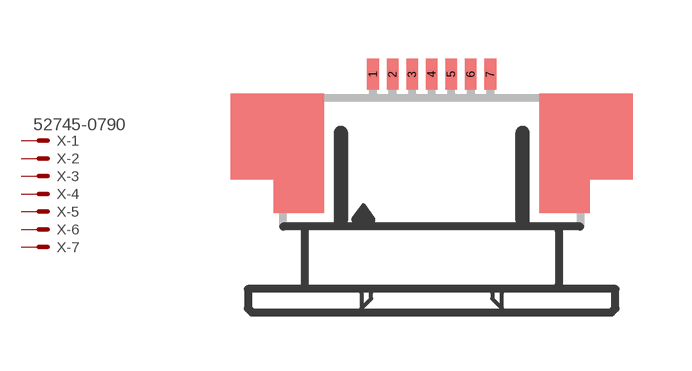
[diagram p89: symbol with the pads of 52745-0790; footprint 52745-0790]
Designator prefix X; gates -1=MV -2=M -3=M -4=M -5=M -6=M -7=M

## 52745-0790 (OC_FARNELL: unknown; OC_NEWARK: unknown)  [52745-0790]
1  -1:S  pas
2  -2:S  pas
3  -3:S  pas
4  -4:S  pas
5  -5:S  pas
6  -6:S  pas
7  -7:S  pas

## Footprint 52745-0790 (pad centres in mm)
FFC/FPC-to-Board 0.50mm (.020") SMT Top Contact Right Angle, ZIF, Style Receptacle 52745 / 52435 Source: http://www.molex.com/product/ffc/52745.html
smd 0.3 x 0.8: 1 -1.5,2.5; 2 -1,2.5; 3 -0.5,2.5; 4 0,2.5; 5 0.5,2.5; 6 1,2.5; 7 1.5,2.5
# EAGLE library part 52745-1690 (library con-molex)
FFC/FPC-to-Board 0.50mm (.020") SMT Top Contact Right Angle, ZIF, Style Receptacle 52745 / 52435 Source: http://www.molex.com/product/ffc/52745.html

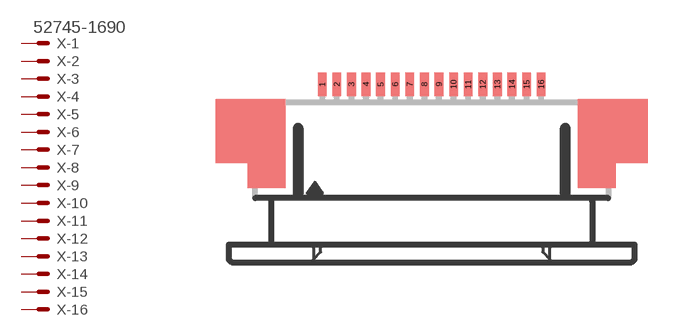
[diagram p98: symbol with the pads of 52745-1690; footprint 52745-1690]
Designator prefix X; gates -1=MV -2=M -3=M -4=M -5=M -6=M -7=M -8=M -9=M -10=M -11=M -12=M -13=M -14=M -15=M -16=M

## 52745-1690 (MF: MOLEX; MPN: 52745-1690; OC_FARNELL: unknown; OC_NEWARK: 57H4224)  [52745-1690]
1  -1:S  pas
2  -2:S  pas
3  -3:S  pas
4  -4:S  pas
5  -5:S  pas
6  -6:S  pas
7  -7:S  pas
8  -8:S  pas
9  -9:S  pas
10  -10:S  pas
11  -11:S  pas
12  -12:S  pas
13  -13:S  pas
14  -14:S  pas
15  -15:S  pas
16  -16:S  pas

## Footprint 52745-1690 (pad centres in mm)
FFC/FPC-to-Board 0.50mm (.020") SMT Top Contact Right Angle, ZIF, Style Receptacle 52745 / 52435 Source: http://www.molex.com/product/ffc/52745.html
smd 0.3 x 0.8: 1 -3.75,2.5; 2 -3.25,2.5; 3 -2.75,2.5; 4 -2.25,2.5; 5 -1.75,2.5; 6 -1.25,2.5; 7 -0.75,2.5; 8 -0.25,2.5; 9 0.25,2.5; 10 0.75,2.5; 11 1.25,2.5; 12 1.75,2.5; 13 2.25,2.5; 14 2.75,2.5; 15 3.25,2.5; 16 3.75,2.5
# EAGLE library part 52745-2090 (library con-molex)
FFC/FPC-to-Board 0.50mm (.020") SMT Top Contact Right Angle, ZIF, Style Receptacle 52745 / 52435 Source: http://www.molex.com/product/ffc/52745.html

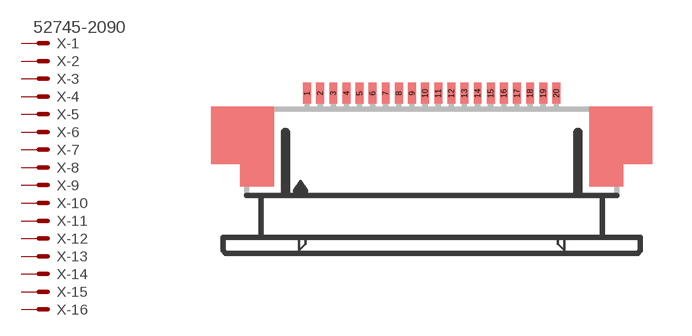
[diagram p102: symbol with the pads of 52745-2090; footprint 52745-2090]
Designator prefix X; gates -1=MV -2=M -3=M -4=M -5=M -6=M -7=M -8=M -9=M -10=M -11=M -12=M -13=M -14=M -15=M -16=M -17=M -18=M -19=M -20=M

## 52745-2090 (MF: WALDOM/MOLEX; MPN: 52745-2090; OC_FARNELL: unknown; OC_NEWARK: 38C9891)  [52745-2090]
1  -1:S  pas
2  -2:S  pas
3  -3:S  pas
4  -4:S  pas
5  -5:S  pas
6  -6:S  pas
7  -7:S  pas
8  -8:S  pas
9  -9:S  pas
10  -10:S  pas
11  -11:S  pas
12  -12:S  pas
13  -13:S  pas
14  -14:S  pas
15  -15:S  pas
16  -16:S  pas
17  -17:S  pas
18  -18:S  pas
19  -19:S  pas
20  -20:S  pas

## Footprint 52745-2090 (pad centres in mm)
FFC/FPC-to-Board 0.50mm (.020") SMT Top Contact Right Angle, ZIF, Style Receptacle 52745 / 52435 Source: http://www.molex.com/product/ffc/52745.html
smd 0.3 x 0.8: 1 -4.75,2.5; 2 -4.25,2.5; 3 -3.75,2.5; 4 -3.25,2.5; 5 -2.75,2.5; 6 -2.25,2.5; 7 -1.75,2.5; 8 -1.25,2.5; 9 -0.75,2.5; 10 -0.25,2.5; 11 0.25,2.5; 12 0.75,2.5; 13 1.25,2.5; 14 1.75,2.5; 15 2.25,2.5; 16 2.75,2.5; 17 3.25,2.5; 18 3.75,2.5; 19 4.25,2.5; 20 4.75,2.5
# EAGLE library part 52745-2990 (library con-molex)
FFC/FPC-to-Board 0.50mm (.020") SMT Top Contact Right Angle, ZIF, Style Receptacle 52745 / 52435 Source: http://www.molex.com/product/ffc/52745.html

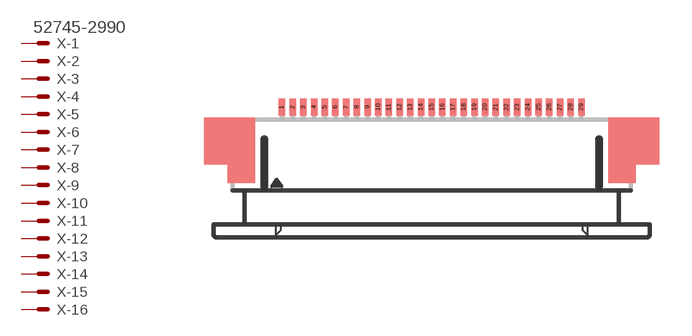
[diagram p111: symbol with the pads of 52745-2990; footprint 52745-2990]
Designator prefix X; gates -1=MV -2=M -3=M -4=M -5=M -6=M -7=M -8=M -9=M -10=M -11=M -12=M -13=M -14=M -15=M -16=M -17=M -18=M -19=M -20=M -21=M -22=M -23=M -24=M -25=M -26=M -27=M -28=M -29=M

## 52745-2990 (OC_FARNELL: unknown; OC_NEWARK: unknown)  [52745-2990]
1  -1:S  pas
2  -2:S  pas
3  -3:S  pas
4  -4:S  pas
5  -5:S  pas
6  -6:S  pas
7  -7:S  pas
8  -8:S  pas
9  -9:S  pas
10  -10:S  pas
11  -11:S  pas
12  -12:S  pas
13  -13:S  pas
14  -14:S  pas
15  -15:S  pas
16  -16:S  pas
17  -17:S  pas
18  -18:S  pas
19  -19:S  pas
20  -20:S  pas
21  -21:S  pas
22  -22:S  pas
23  -23:S  pas
24  -24:S  pas
25  -25:S  pas
26  -26:S  pas
27  -27:S  pas
28  -28:S  pas
29  -29:S  pas

## Footprint 52745-2990 (pad centres in mm)
FFC/FPC-to-Board 0.50mm (.020") SMT Top Contact Right Angle, ZIF, Style Receptacle 52745 / 52435 Source: http://www.molex.com/product/ffc/52745.html
smd 0.3 x 0.8: 1 -7,2.5; 2 -6.5,2.5; 3 -6,2.5; 4 -5.5,2.5; 5 -5,2.5; 6 -4.5,2.5; 7 -4,2.5; 8 -3.5,2.5; 9 -3,2.5; 10 -2.5,2.5; 11 -2,2.5; 12 -1.5,2.5; 13 -1,2.5; 14 -0.5,2.5; 15 0,2.5; 16 0.5,2.5; 17 1,2.5; 18 1.5,2.5; 19 2,2.5; 20 2.5,2.5; 21 3,2.5; 22 3.5,2.5; 23 4,2.5; 24 4.5,2.5; 25 5,2.5; 26 5.5,2.5; 27 6,2.5; 28 6.5,2.5; 29 7,2.5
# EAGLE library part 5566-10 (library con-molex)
Mini FIT connector 10 pol Source: http://www.molex.com

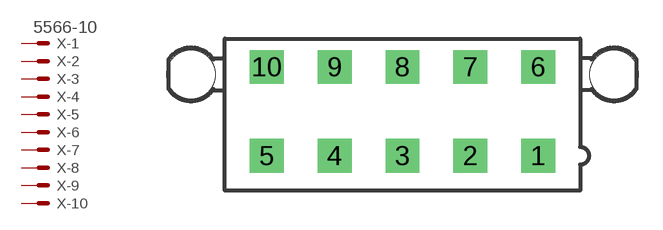
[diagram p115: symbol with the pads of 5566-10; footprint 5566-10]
Designator prefix X; gates -1=MV -2=M -3=M -4=M -5=M -6=M -7=M -8=M -9=M -10=M

## 5566-10 (OC_FARNELL: unknown; OC_NEWARK: unknown)  [5566-10]
1  -1:S  pas
2  -2:S  pas
3  -3:S  pas
4  -4:S  pas
5  -5:S  pas
6  -6:S  pas
7  -7:S  pas
8  -8:S  pas
9  -9:S  pas
10  -10:S  pas

## Footprint 5566-10 (pad centres in mm)
Mini FIT connector 10 pol Source: http://www.molex.com
drill 1.4 square: 1 8.4,-2.75; 2 4.2,-2.75; 3 0,-2.75; 4 -4.2,-2.75; 5 -8.4,-2.75; 6 8.4,2.75; 7 4.2,2.75; 8 0,2.75; 9 -4.2,2.75; 10 -8.4,2.75
hole 3 at 13.1,2.29
hole 3 at -13.1,2.29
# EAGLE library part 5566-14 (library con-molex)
Mini FIT connector 14 pol Source: http://www.molex.com

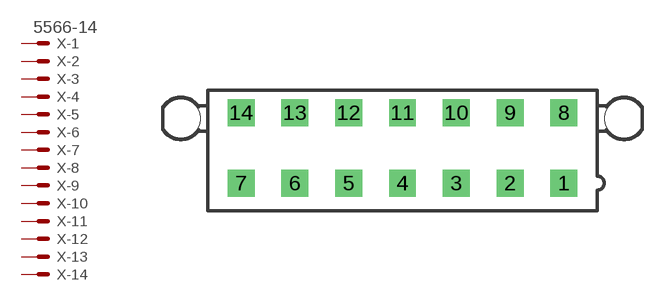
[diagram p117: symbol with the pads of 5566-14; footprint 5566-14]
Designator prefix X; gates -1=MV -2=M -3=M -4=M -5=M -6=M -7=M -8=M -9=M -10=M -11=M -12=M -13=M -14=M

## 5566-14 (OC_FARNELL: unknown; OC_NEWARK: unknown)  [5566-14]
1  -1:S  pas
2  -2:S  pas
3  -3:S  pas
4  -4:S  pas
5  -5:S  pas
6  -6:S  pas
7  -7:S  pas
8  -8:S  pas
9  -9:S  pas
10  -10:S  pas
11  -11:S  pas
12  -12:S  pas
13  -13:S  pas
14  -14:S  pas

## Footprint 5566-14 (pad centres in mm)
Mini FIT connector 14 pol Source: http://www.molex.com
drill 1.4 square: 1 12.6,-2.75; 2 8.4,-2.75; 3 4.2,-2.75; 4 0,-2.75; 5 -4.2,-2.75; 6 -8.4,-2.75; 7 -12.6,-2.75; 8 12.6,2.75; 9 8.4,2.75; 10 4.2,2.75; 11 0,2.75; 12 -4.2,2.75; 13 -8.4,2.75; 14 -12.6,2.75
hole 3 at 17.3,2.29
hole 3 at -17.3,2.29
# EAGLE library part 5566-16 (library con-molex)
Mini FIT connector 16 pol Source: http://www.molex.com

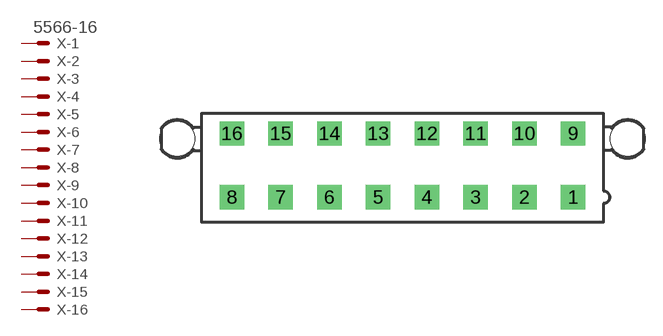
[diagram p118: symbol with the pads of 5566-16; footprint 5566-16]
Designator prefix X; gates -1=MV -2=M -3=M -4=M -5=M -6=M -7=M -8=M -9=M -10=M -11=M -12=M -13=M -14=M -15=M -16=M

## 5566-16 (OC_FARNELL: unknown; OC_NEWARK: unknown)  [5566-16]
1  -1:S  pas
2  -2:S  pas
3  -3:S  pas
4  -4:S  pas
5  -5:S  pas
6  -6:S  pas
7  -7:S  pas
8  -8:S  pas
9  -9:S  pas
10  -10:S  pas
11  -11:S  pas
12  -12:S  pas
13  -13:S  pas
14  -14:S  pas
15  -15:S  pas
16  -16:S  pas

## Footprint 5566-16 (pad centres in mm)
Mini FIT connector 16 pol Source: http://www.molex.com
drill 1.4 square: 1 14.7,-2.75; 2 10.5,-2.75; 3 6.3,-2.75; 4 2.1,-2.75; 5 -2.1,-2.75; 6 -6.3,-2.75; 7 -10.5,-2.75; 8 -14.7,-2.75; 9 14.7,2.75; 10 10.5,2.75; 11 6.3,2.75; 12 2.1,2.75; 13 -2.1,2.75; 14 -6.3,2.75; 15 -10.5,2.75; 16 -14.7,2.75
hole 3 at 19.4,2.29
hole 3 at -19.4,2.29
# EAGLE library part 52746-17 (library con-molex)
FPC Connector ZIF for SMT 0.5mm Source: http://www.farnell.com/datasheets/73044.pdf [DWG. NO. (Sheet 1 OF 2) SD-52746-**17]

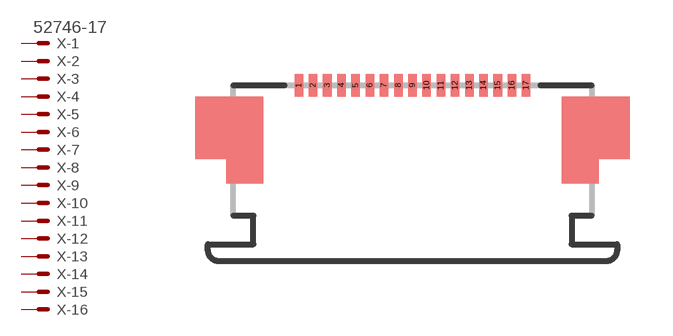
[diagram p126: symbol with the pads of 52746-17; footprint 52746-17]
Designator prefix X; gates -1=MV -2=M -3=M -4=M -5=M -6=M -7=M -8=M -9=M -10=M -11=M -12=M -13=M -14=M -15=M -16=M -17=M

## 52746-17 (MPN: 52746-1770; OC_FARNELL: unknown; OC_NEWARK: 92M6419)  [52746-17]
1  -1:S  pas
2  -2:S  pas
3  -3:S  pas
4  -4:S  pas
5  -5:S  pas
6  -6:S  pas
7  -7:S  pas
8  -8:S  pas
9  -9:S  pas
10  -10:S  pas
11  -11:S  pas
12  -12:S  pas
13  -13:S  pas
14  -14:S  pas
15  -15:S  pas
16  -16:S  pas
17  -17:S  pas

## Footprint 52746-17 (pad centres in mm)
FPC Connector ZIF for SMT 0.5mm Source: http://www.farnell.com/datasheets/73044.pdf [DWG. NO. (Sheet 1 OF 2) SD-52746-**17]
smd 0.3 x 0.8: 1 -4,0.6; 2 -3.5,0.6; 3 -3,0.6; 4 -2.5,0.6; 5 -2,0.6; 6 -1.5,0.6; 7 -1,0.6; 8 -0.5,0.6; 9 0,0.6; 10 0.5,0.6; 11 1,0.6; 12 1.5,0.6; 13 2,0.6; 14 2.5,0.6; 15 3,0.6; 16 3.5,0.6; 17 4,0.6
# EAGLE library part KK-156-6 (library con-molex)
KK 156 HEADER Source: http://www.molex.com/pdm_docs/sd/026604100_sd.pdf

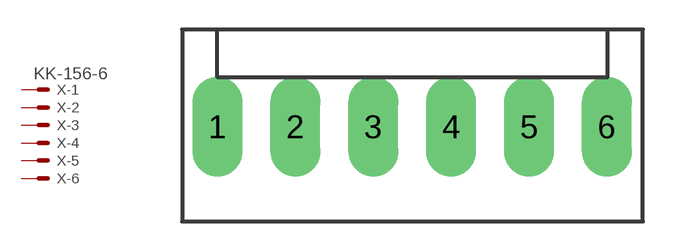
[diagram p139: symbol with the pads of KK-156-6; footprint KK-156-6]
Designator prefix X; gates -1=MV -2=M -3=M -4=M -5=M -6=M

## KK-156-6 (OC_FARNELL: unknown; OC_NEWARK: unknown)  [KK-156-6]
1  -1:S  pas
2  -2:S  pas
3  -3:S  pas
4  -4:S  pas
5  -5:S  pas
6  -6:S  pas

## Footprint KK-156-6 (pad centres in mm)
KK 156 HEADER Source: http://www.molex.com/pdm_docs/sd/026604100_sd.pdf
drill 1.7 pad 2.184 long: 1 -9.9,0; 2 -5.94,0; 3 -1.98,0; 4 1.98,0; 5 5.94,0; 6 9.9,0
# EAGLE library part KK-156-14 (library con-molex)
KK 156 HEADER Source: http://www.molex.com/pdm_docs/sd/026604100_sd.pdf

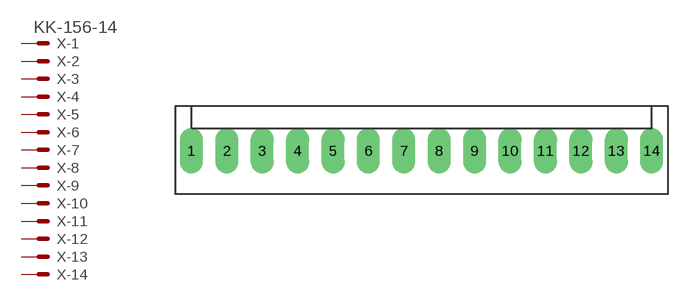
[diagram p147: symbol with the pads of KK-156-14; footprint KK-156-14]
Designator prefix X; gates -1=MV -2=M -3=M -4=M -5=M -6=M -7=M -8=M -9=M -10=M -11=M -12=M -13=M -14=M

## KK-156-14 (OC_FARNELL: unknown; OC_NEWARK: unknown)  [KK-156-14]
1  -1:S  pas
2  -2:S  pas
3  -3:S  pas
4  -4:S  pas
5  -5:S  pas
6  -6:S  pas
7  -7:S  pas
8  -8:S  pas
9  -9:S  pas
10  -10:S  pas
11  -11:S  pas
12  -12:S  pas
13  -13:S  pas
14  -14:S  pas

## Footprint KK-156-14 (pad centres in mm)
KK 156 HEADER Source: http://www.molex.com/pdm_docs/sd/026604100_sd.pdf
drill 1.7 pad 2.184 long: 1 -25.74,0; 2 -21.78,0; 3 -17.82,0; 4 -13.86,0; 5 -9.9,0; 6 -5.94,0; 7 -1.98,0; 8 1.98,0; 9 5.94,0; 10 9.9,0; 11 13.86,0; 12 17.82,0; 13 21.78,0; 14 25.74,0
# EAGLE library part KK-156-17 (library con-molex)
KK 156 HEADER Source: http://www.molex.com/pdm_docs/sd/026604100_sd.pdf

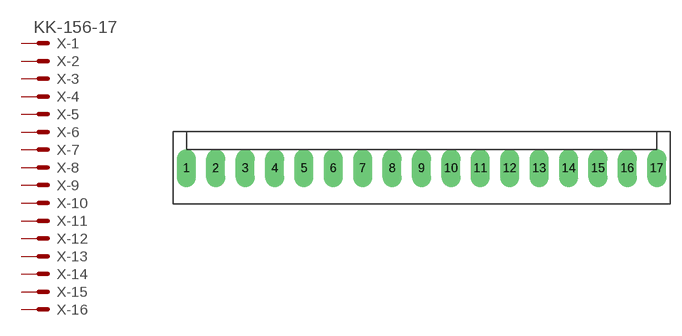
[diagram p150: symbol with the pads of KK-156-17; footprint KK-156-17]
Designator prefix X; gates -1=MV -2=M -3=M -4=M -5=M -6=M -7=M -8=M -9=M -10=M -11=M -12=M -13=M -14=M -15=M -16=M -17=M

## KK-156-17 (OC_FARNELL: unknown; OC_NEWARK: unknown)  [KK-156-17]
1  -1:S  pas
2  -2:S  pas
3  -3:S  pas
4  -4:S  pas
5  -5:S  pas
6  -6:S  pas
7  -7:S  pas
8  -8:S  pas
9  -9:S  pas
10  -10:S  pas
11  -11:S  pas
12  -12:S  pas
13  -13:S  pas
14  -14:S  pas
15  -15:S  pas
16  -16:S  pas
17  -17:S  pas

## Footprint KK-156-17 (pad centres in mm)
KK 156 HEADER Source: http://www.molex.com/pdm_docs/sd/026604100_sd.pdf
drill 1.7 pad 2.184 long: 1 -31.68,0; 2 -27.72,0; 3 -23.76,0; 4 -19.8,0; 5 -15.84,0; 6 -11.88,0; 7 -7.92,0; 8 -3.96,0; 9 0,0; 10 3.96,0; 11 7.92,0; 12 11.88,0; 13 15.84,0; 14 19.8,0; 15 23.76,0; 16 27.72,0; 17 31.68,0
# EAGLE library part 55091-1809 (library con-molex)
0.635 mm PITCH B TO B CONN. Source: http://www.molex.com/pdm_docs/sd/550911609_sd.pdf

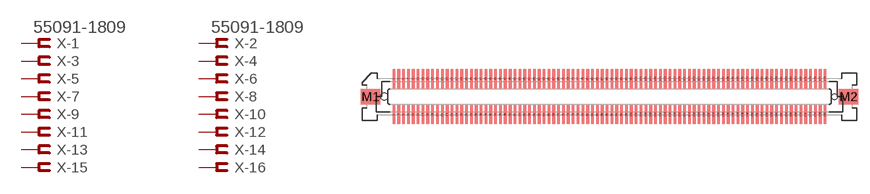
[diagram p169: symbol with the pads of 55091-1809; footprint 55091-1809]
Designator prefix X; gates -1=FV -2=FV -3=F -4=F -5=F -6=F -7=F -8=F -9=F -10=F -11=F -12=F -13=F -14=F -15=F -16=F -17=F -18=F -19=F -20=F -21=F -22=F -23=F -24=F -25=F -26=F -27=F -28=F -29=F -30=F -31=F -32=F -33=F -34=F -35=F -36=F -37=F -38=F -39=F -40=F -41=F -42=F -43=F -44=F -45=F -46=F -47=F -48=F -49=F -50=F -51=F -52=F -53=F -54=F -55=F -56=F -57=F -58=F -59=F -60=F -61=F -62=F -63=F -64=F -65=F -66=F -67=F -68=F -69=F -70=F -71=F -72=F -73=F -74=F -75=F -76=F -77=F -78=F -79=F -80=F -81=F -82=F -83=F -84=F -85=F -86=F -87=F -88=F -89=F -90=F -91=F -92=F -93=F -94=F -95=F -96=F -97=F -98=F -99=F -100=F -101=F -102=F -103=F -104=F -105=F -106=F -107=F -108=F -109=F -110=F -111=F -112=F -113=F -114=F -115=F -116=F -117=F -118=F -119=F -120=F -121=F -122=F -123=F -124=F -125=F -126=F -127=F -128=F -129=F -130=F -131=F -132=F -133=F -134=F -135=F -136=F -137=F -138=F -139=F -140=F -141=F -142=F -143=F -144=F -145=F -146=F -147=F -148=F -149=F -150=F -151=F -152=F -153=F -154=F -155=F -156=F -157=F -158=F -159=F -160=F -161=F -162=F -163=F -164=F -165=F -166=F -167=F -168=F -169=F -170=F -171=F -172=F -173=F -174=F -175=F -176=F -177=F -178=F -179=F -180=F

## 55091-1809 (OC_FARNELL: unknown; OC_NEWARK: unknown)  [55091-1809]
1  -1:S  pas
2  -2:S  pas
3  -3:S  pas
4  -4:S  pas
5  -5:S  pas
6  -6:S  pas
7  -7:S  pas
8  -8:S  pas
9  -9:S  pas
10  -10:S  pas
11  -11:S  pas
12  -12:S  pas
13  -13:S  pas
14  -14:S  pas
15  -15:S  pas
16  -16:S  pas
17  -17:S  pas
18  -18:S  pas
19  -19:S  pas
20  -20:S  pas
21  -21:S  pas
22  -22:S  pas
23  -23:S  pas
24  -24:S  pas
25  -25:S  pas
26  -26:S  pas
27  -27:S  pas
28  -28:S  pas
29  -29:S  pas
30  -30:S  pas
31  -31:S  pas
32  -32:S  pas
33  -33:S  pas
34  -34:S  pas
35  -35:S  pas
36  -36:S  pas
37  -37:S  pas
38  -38:S  pas
39  -39:S  pas
40  -40:S  pas
41  -41:S  pas
42  -42:S  pas
43  -43:S  pas
44  -44:S  pas
45  -45:S  pas
46  -46:S  pas
47  -47:S  pas
48  -48:S  pas
49  -49:S  pas
50  -50:S  pas
51  -51:S  pas
52  -52:S  pas
53  -53:S  pas
54  -54:S  pas
55  -55:S  pas
56  -56:S  pas
57  -57:S  pas
58  -58:S  pas
59  -59:S  pas
60  -60:S  pas
61  -61:S  pas
62  -62:S  pas
63  -63:S  pas
64  -64:S  pas
65  -65:S  pas
66  -66:S  pas
67  -67:S  pas
68  -68:S  pas
69  -69:S  pas
70  -70:S  pas
71  -71:S  pas
72  -72:S  pas
73  -73:S  pas
74  -74:S  pas
75  -75:S  pas
76  -76:S  pas
77  -77:S  pas
78  -78:S  pas
79  -79:S  pas
80  -80:S  pas
81  -81:S  pas
82  -82:S  pas
83  -83:S  pas
84  -84:S  pas
85  -85:S  pas
86  -86:S  pas
87  -87:S  pas
88  -88:S  pas
89  -89:S  pas
90  -90:S  pas
91  -91:S  pas
92  -92:S  pas
93  -93:S  pas
94  -94:S  pas
95  -95:S  pas
96  -96:S  pas
97  -97:S  pas
98  -98:S  pas
99  -99:S  pas
100  -100:S  pas
101  -101:S  pas
102  -102:S  pas
103  -103:S  pas
104  -104:S  pas
105  -105:S  pas
106  -106:S  pas
107  -107:S  pas
108  -108:S  pas
109  -109:S  pas
110  -110:S  pas
111  -111:S  pas
112  -112:S  pas
113  -113:S  pas
114  -114:S  pas
115  -115:S  pas
116  -116:S  pas
117  -117:S  pas
118  -118:S  pas
119  -119:S  pas
120  -120:S  pas
121  -121:S  pas
122  -122:S  pas
123  -123:S  pas
124  -124:S  pas
125  -125:S  pas
126  -126:S  pas
127  -127:S  pas
128  -128:S  pas
129  -129:S  pas
130  -130:S  pas
131  -131:S  pas
132  -132:S  pas
133  -133:S  pas
134  -134:S  pas
135  -135:S  pas
136  -136:S  pas
137  -137:S  pas
138  -138:S  pas
139  -139:S  pas
140  -140:S  pas
141  -141:S  pas
142  -142:S  pas
143  -143:S  pas
144  -144:S  pas
145  -145:S  pas
146  -146:S  pas
147  -147:S  pas
148  -148:S  pas
149  -149:S  pas
150  -150:S  pas
151  -151:S  pas
152  -152:S  pas
153  -153:S  pas
154  -154:S  pas
155  -155:S  pas
156  -156:S  pas
157  -157:S  pas
158  -158:S  pas
159  -159:S  pas
160  -160:S  pas
161  -161:S  pas
162  -162:S  pas
163  -163:S  pas
164  -164:S  pas
165  -165:S  pas
166  -166:S  pas
167  -167:S  pas
168  -168:S  pas
169  -169:S  pas
170  -170:S  pas
171  -171:S  pas
172  -172:S  pas
173  -173:S  pas
174  -174:S  pas
175  -175:S  pas
176  -176:S  pas
177  -177:S  pas
178  -178:S  pas
179  -179:S  pas
180  -180:S  pas

## Footprint 55091-1809 (pad centres in mm)
0.635 mm PITCH B TO B CONN. Source: http://www.molex.com/pdm_docs/sd/550911609_sd.pdf
smd 0.35 x 2.5: 1 -28.258,2.35; 2 -28.258,-2.35; 3 -27.622,2.35; 4 -27.622,-2.35; 5 -26.988,2.35; 6 -26.988,-2.35; 7 -26.352,2.35; 8 -26.352,-2.35; 9 -25.718,2.35; 10 -25.718,-2.35; 11 -25.082,2.35; 12 -25.082,-2.35; 13 -24.448,2.35; 14 -24.448,-2.35; 15 -23.812,2.35; 16 -23.812,-2.35; 17 -23.177,2.35; 18 -23.177,-2.35; 19 -22.543,2.35; 20 -22.543,-2.35; 21 -21.907,2.35; 22 -21.907,-2.35; 23 -21.273,2.35; 24 -21.273,-2.35; 25 -20.637,2.35; 26 -20.637,-2.35; 27 -20.003,2.35; 28 -20.003,-2.35; 29 -19.367,2.35; 30 -19.367,-2.35; 31 -18.733,2.35; 32 -18.733,-2.35; 33 -18.098,2.35; 34 -18.098,-2.35; 35 -17.462,2.35; 36 -17.462,-2.35; 37 -16.828,2.35; 38 -16.828,-2.35; 39 -16.192,2.35; 40 -16.192,-2.35; 41 -15.557,2.35; 42 -15.557,-2.35; 43 -14.922,2.35; 44 -14.922,-2.35; 45 -14.287,2.35; 46 -14.287,-2.35; 47 -13.652,2.35; 48 -13.652,-2.35; 49 -13.018,2.35; 50 -13.018,-2.35; 51 -12.383,2.35; 52 -12.383,-2.35; 53 -11.748,2.35; 54 -11.748,-2.35; 55 -11.113,2.35; 56 -11.113,-2.35; 57 -10.477,2.35; 58 -10.477,-2.35; 59 -9.842,2.35; 60 -9.842,-2.35; 61 -9.207,2.35; 62 -9.207,-2.35; 63 -8.572,2.35; 64 -8.572,-2.35; 65 -7.938,2.35; 66 -7.938,-2.35; 67 -7.303,2.35; 68 -7.303,-2.35; 69 -6.668,2.35; 70 -6.668,-2.35; 71 -6.032,2.35; 72 -6.032,-2.35; 73 -5.397,2.35; 74 -5.397,-2.35; 75 -4.763,2.35; 76 -4.763,-2.35; 77 -4.128,2.35; 78 -4.128,-2.35; 79 -3.493,2.35; 80 -3.493,-2.35; 81 -2.857,2.35; 82 -2.857,-2.35; 83 -2.223,2.35; 84 -2.223,-2.35; 85 -1.587,2.35; 86 -1.587,-2.35; 87 -0.953,2.35; 88 -0.953,-2.35; 89 -0.318,2.35; 90 -0.318,-2.35; 91 0.318,2.35; 92 0.318,-2.35; 93 0.953,2.35; 94 0.953,-2.35; 95 1.587,2.35; 96 1.587,-2.35; 97 2.223,2.35; 98 2.223,-2.35; 99 2.857,2.35; 100 2.857,-2.35; 101 3.493,2.35; 102 3.493,-2.35; 103 4.128,2.35; 104 4.128,-2.35; 105 4.763,2.35; 106 4.763,-2.35; 107 5.397,2.35; 108 5.397,-2.35; 109 6.032,2.35; 110 6.032,-2.35; 111 6.668,2.35; 112 6.668,-2.35; 113 7.303,2.35; 114 7.303,-2.35; 115 7.938,2.35; 116 7.938,-2.35; 117 8.572,2.35; 118 8.572,-2.35; 119 9.207,2.35; 120 9.207,-2.35; 121 9.842,2.35; 122 9.842,-2.35; 123 10.477,2.35; 124 10.477,-2.35; 125 11.113,2.35; 126 11.113,-2.35; 127 11.748,2.35; 128 11.748,-2.35; 129 12.383,2.35; 130 12.383,-2.35; 131 13.018,2.35; 132 13.018,-2.35; 133 13.652,2.35; 134 13.652,-2.35; 135 14.287,2.35; 136 14.287,-2.35; 137 14.922,2.35; 138 14.922,-2.35; 139 15.557,2.35; 140 15.557,-2.35; 141 16.192,2.35; 142 16.192,-2.35; 143 16.828,2.35; 144 16.828,-2.35; 145 17.462,2.35; 146 17.462,-2.35; 147 18.098,2.35; 148 18.098,-2.35; 149 18.733,2.35; 150 18.733,-2.35; 151 19.367,2.35; 152 19.367,-2.35; 153 20.003,2.35; 154 20.003,-2.35; 155 20.637,2.35; 156 20.637,-2.35; 157 21.273,2.35; 158 21.273,-2.35; 159 21.907,2.35; 160 21.907,-2.35; 161 22.543,2.35; 162 22.543,-2.35; 163 23.177,2.35; 164 23.177,-2.35; 165 23.812,2.35; 166 23.812,-2.35; 167 24.448,2.35; 168 24.448,-2.35; 169 25.082,2.35; 170 25.082,-2.35; 171 25.718,2.35; 172 25.718,-2.35; 173 26.352,2.35; 174 26.352,-2.35; 175 26.988,2.35; 176 26.988,-2.35; 177 27.622,2.35; 178 27.622,-2.35; 179 28.258,2.35; 180 28.258,-2.35
smd 2.5 x 2: M1 -31.325,0; M2 31.325,0
hole 0.9 at -29.51,0
hole 0.7 at 29.51,0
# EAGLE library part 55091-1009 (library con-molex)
0.635 mm PITCH B TO B CONN. Source: http://www.molex.com/pdm_docs/sd/550911609_sd.pdf

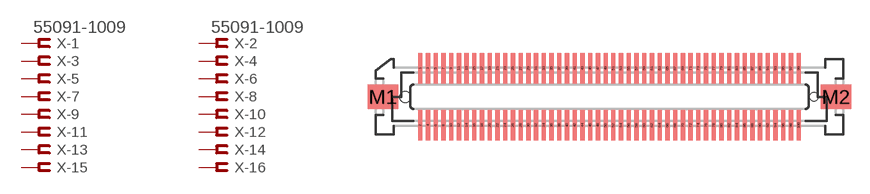
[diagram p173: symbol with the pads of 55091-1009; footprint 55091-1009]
Designator prefix X; gates -1=FV -2=FV -3=F -4=F -5=F -6=F -7=F -8=F -9=F -10=F -11=F -12=F -13=F -14=F -15=F -16=F -17=F -18=F -19=F -20=F -21=F -22=F -23=F -24=F -25=F -26=F -27=F -28=F -29=F -30=F -31=F -32=F -33=F -34=F -35=F -36=F -37=F -38=F -39=F -40=F -41=F -42=F -43=F -44=F -45=F -46=F -47=F -48=F -49=F -50=F -51=F -52=F -53=F -54=F -55=F -56=F -57=F -58=F -59=F -60=F -61=F -62=F -63=F -64=F -65=F -66=F -67=F -68=F -69=F -70=F -71=F -72=F -73=F -74=F -75=F -76=F -77=F -78=F -79=F -80=F -81=F -82=F -83=F -84=F -85=F -86=F -87=F -88=F -89=F -90=F -91=F -92=F -93=F -94=F -95=F -96=F -97=F -98=F -99=F -100=F

## 55091-1009 (OC_FARNELL: unknown; OC_NEWARK: unknown)  [55091-1009]
1  -1:S  pas
2  -2:S  pas
3  -3:S  pas
4  -4:S  pas
5  -5:S  pas
6  -6:S  pas
7  -7:S  pas
8  -8:S  pas
9  -9:S  pas
10  -10:S  pas
11  -11:S  pas
12  -12:S  pas
13  -13:S  pas
14  -14:S  pas
15  -15:S  pas
16  -16:S  pas
17  -17:S  pas
18  -18:S  pas
19  -19:S  pas
20  -20:S  pas
21  -21:S  pas
22  -22:S  pas
23  -23:S  pas
24  -24:S  pas
25  -25:S  pas
26  -26:S  pas
27  -27:S  pas
28  -28:S  pas
29  -29:S  pas
30  -30:S  pas
31  -31:S  pas
32  -32:S  pas
33  -33:S  pas
34  -34:S  pas
35  -35:S  pas
36  -36:S  pas
37  -37:S  pas
38  -38:S  pas
39  -39:S  pas
40  -40:S  pas
41  -41:S  pas
42  -42:S  pas
43  -43:S  pas
44  -44:S  pas
45  -45:S  pas
46  -46:S  pas
47  -47:S  pas
48  -48:S  pas
49  -49:S  pas
50  -50:S  pas
51  -51:S  pas
52  -52:S  pas
53  -53:S  pas
54  -54:S  pas
55  -55:S  pas
56  -56:S  pas
57  -57:S  pas
58  -58:S  pas
59  -59:S  pas
60  -60:S  pas
61  -61:S  pas
62  -62:S  pas
63  -63:S  pas
64  -64:S  pas
65  -65:S  pas
66  -66:S  pas
67  -67:S  pas
68  -68:S  pas
69  -69:S  pas
70  -70:S  pas
71  -71:S  pas
72  -72:S  pas
73  -73:S  pas
74  -74:S  pas
75  -75:S  pas
76  -76:S  pas
77  -77:S  pas
78  -78:S  pas
79  -79:S  pas
80  -80:S  pas
81  -81:S  pas
82  -82:S  pas
83  -83:S  pas
84  -84:S  pas
85  -85:S  pas
86  -86:S  pas
87  -87:S  pas
88  -88:S  pas
89  -89:S  pas
90  -90:S  pas
91  -91:S  pas
92  -92:S  pas
93  -93:S  pas
94  -94:S  pas
95  -95:S  pas
96  -96:S  pas
97  -97:S  pas
98  -98:S  pas
99  -99:S  pas
100  -100:S  pas

## Footprint 55091-1009 (pad centres in mm)
0.635 mm PITCH B TO B CONN. Source: http://www.molex.com/pdm_docs/sd/550911609_sd.pdf
smd 0.35 x 2.5: 1 -15.557,2.35; 2 -15.557,-2.35; 3 -14.922,2.35; 4 -14.922,-2.35; 5 -14.287,2.35; 6 -14.287,-2.35; 7 -13.652,2.35; 8 -13.652,-2.35; 9 -13.018,2.35; 10 -13.018,-2.35; 11 -12.383,2.35; 12 -12.383,-2.35; 13 -11.748,2.35; 14 -11.748,-2.35; 15 -11.113,2.35; 16 -11.113,-2.35; 17 -10.477,2.35; 18 -10.477,-2.35; 19 -9.842,2.35; 20 -9.842,-2.35; 21 -9.207,2.35; 22 -9.207,-2.35; 23 -8.572,2.35; 24 -8.572,-2.35; 25 -7.938,2.35; 26 -7.938,-2.35; 27 -7.303,2.35; 28 -7.303,-2.35; 29 -6.668,2.35; 30 -6.668,-2.35; 31 -6.032,2.35; 32 -6.032,-2.35; 33 -5.397,2.35; 34 -5.397,-2.35; 35 -4.763,2.35; 36 -4.763,-2.35; 37 -4.128,2.35; 38 -4.128,-2.35; 39 -3.493,2.35; 40 -3.493,-2.35; 41 -2.857,2.35; 42 -2.857,-2.35; 43 -2.223,2.35; 44 -2.223,-2.35; 45 -1.587,2.35; 46 -1.587,-2.35; 47 -0.953,2.35; 48 -0.953,-2.35; 49 -0.318,2.35; 50 -0.318,-2.35; 51 0.318,2.35; 52 0.318,-2.35; 53 0.953,2.35; 54 0.953,-2.35; 55 1.587,2.35; 56 1.587,-2.35; 57 2.223,2.35; 58 2.223,-2.35; 59 2.857,2.35; 60 2.857,-2.35; 61 3.493,2.35; 62 3.493,-2.35; 63 4.128,2.35; 64 4.128,-2.35; 65 4.763,2.35; 66 4.763,-2.35; 67 5.397,2.35; 68 5.397,-2.35; 69 6.032,2.35; 70 6.032,-2.35; 71 6.668,2.35; 72 6.668,-2.35; 73 7.303,2.35; 74 7.303,-2.35; 75 7.938,2.35; 76 7.938,-2.35; 77 8.572,2.35; 78 8.572,-2.35; 79 9.207,2.35; 80 9.207,-2.35; 81 9.842,2.35; 82 9.842,-2.35; 83 10.477,2.35; 84 10.477,-2.35; 85 11.113,2.35; 86 11.113,-2.35; 87 11.748,2.35; 88 11.748,-2.35; 89 12.383,2.35; 90 12.383,-2.35; 91 13.018,2.35; 92 13.018,-2.35; 93 13.652,2.35; 94 13.652,-2.35; 95 14.287,2.35; 96 14.287,-2.35; 97 14.922,2.35; 98 14.922,-2.35; 99 15.557,2.35; 100 15.557,-2.35
smd 2.5 x 2: M1 -18.625,0; M2 18.625,0
hole 0.9 at -16.81,0
hole 0.7 at 16.81,0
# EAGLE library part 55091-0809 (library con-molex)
0.635 mm PITCH B TO B CONN. Source: http://www.molex.com/pdm_docs/sd/550911609_sd.pdf

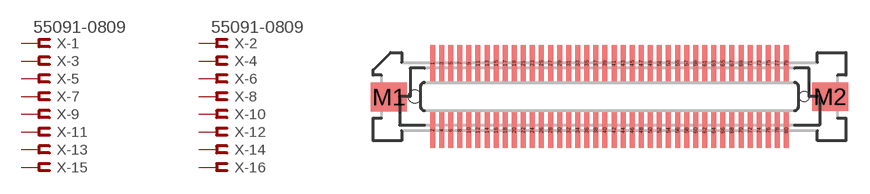
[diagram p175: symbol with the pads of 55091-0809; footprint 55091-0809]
Designator prefix X; gates -1=FV -2=FV -3=F -4=F -5=F -6=F -7=F -8=F -9=F -10=F -11=F -12=F -13=F -14=F -15=F -16=F -17=F -18=F -19=F -20=F -21=F -22=F -23=F -24=F -25=F -26=F -27=F -28=F -29=F -30=F -31=F -32=F -33=F -34=F -35=F -36=F -37=F -38=F -39=F -40=F -41=F -42=F -43=F -44=F -45=F -46=F -47=F -48=F -49=F -50=F -51=F -52=F -53=F -54=F -55=F -56=F -57=F -58=F -59=F -60=F -61=F -62=F -63=F -64=F -65=F -66=F -67=F -68=F -69=F -70=F -71=F -72=F -73=F -74=F -75=F -76=F -77=F -78=F -79=F -80=F

## 55091-0809 (OC_FARNELL: unknown; OC_NEWARK: unknown)  [55091-0809]
1  -1:S  pas
2  -2:S  pas
3  -3:S  pas
4  -4:S  pas
5  -5:S  pas
6  -6:S  pas
7  -7:S  pas
8  -8:S  pas
9  -9:S  pas
10  -10:S  pas
11  -11:S  pas
12  -12:S  pas
13  -13:S  pas
14  -14:S  pas
15  -15:S  pas
16  -16:S  pas
17  -17:S  pas
18  -18:S  pas
19  -19:S  pas
20  -20:S  pas
21  -21:S  pas
22  -22:S  pas
23  -23:S  pas
24  -24:S  pas
25  -25:S  pas
26  -26:S  pas
27  -27:S  pas
28  -28:S  pas
29  -29:S  pas
30  -30:S  pas
31  -31:S  pas
32  -32:S  pas
33  -33:S  pas
34  -34:S  pas
35  -35:S  pas
36  -36:S  pas
37  -37:S  pas
38  -38:S  pas
39  -39:S  pas
40  -40:S  pas
41  -41:S  pas
42  -42:S  pas
43  -43:S  pas
44  -44:S  pas
45  -45:S  pas
46  -46:S  pas
47  -47:S  pas
48  -48:S  pas
49  -49:S  pas
50  -50:S  pas
51  -51:S  pas
52  -52:S  pas
53  -53:S  pas
54  -54:S  pas
55  -55:S  pas
56  -56:S  pas
57  -57:S  pas
58  -58:S  pas
59  -59:S  pas
60  -60:S  pas
61  -61:S  pas
62  -62:S  pas
63  -63:S  pas
64  -64:S  pas
65  -65:S  pas
66  -66:S  pas
67  -67:S  pas
68  -68:S  pas
69  -69:S  pas
70  -70:S  pas
71  -71:S  pas
72  -72:S  pas
73  -73:S  pas
74  -74:S  pas
75  -75:S  pas
76  -76:S  pas
77  -77:S  pas
78  -78:S  pas
79  -79:S  pas
80  -80:S  pas

## Footprint 55091-0809 (pad centres in mm)
0.635 mm PITCH B TO B CONN. Source: http://www.molex.com/pdm_docs/sd/550911609_sd.pdf
smd 0.35 x 2.5: 1 -12.383,2.35; 2 -12.383,-2.35; 3 -11.748,2.35; 4 -11.748,-2.35; 5 -11.113,2.35; 6 -11.113,-2.35; 7 -10.477,2.35; 8 -10.477,-2.35; 9 -9.842,2.35; 10 -9.842,-2.35; 11 -9.207,2.35; 12 -9.207,-2.35; 13 -8.572,2.35; 14 -8.572,-2.35; 15 -7.938,2.35; 16 -7.938,-2.35; 17 -7.303,2.35; 18 -7.303,-2.35; 19 -6.668,2.35; 20 -6.668,-2.35; 21 -6.032,2.35; 22 -6.032,-2.35; 23 -5.397,2.35; 24 -5.397,-2.35; 25 -4.763,2.35; 26 -4.763,-2.35; 27 -4.128,2.35; 28 -4.128,-2.35; 29 -3.493,2.35; 30 -3.493,-2.35; 31 -2.857,2.35; 32 -2.857,-2.35; 33 -2.223,2.35; 34 -2.223,-2.35; 35 -1.587,2.35; 36 -1.587,-2.35; 37 -0.953,2.35; 38 -0.953,-2.35; 39 -0.318,2.35; 40 -0.318,-2.35; 41 0.318,2.35; 42 0.318,-2.35; 43 0.953,2.35; 44 0.953,-2.35; 45 1.587,2.35; 46 1.587,-2.35; 47 2.223,2.35; 48 2.223,-2.35; 49 2.857,2.35; 50 2.857,-2.35; 51 3.493,2.35; 52 3.493,-2.35; 53 4.128,2.35; 54 4.128,-2.35; 55 4.763,2.35; 56 4.763,-2.35; 57 5.397,2.35; 58 5.397,-2.35; 59 6.032,2.35; 60 6.032,-2.35; 61 6.668,2.35; 62 6.668,-2.35; 63 7.303,2.35; 64 7.303,-2.35; 65 7.938,2.35; 66 7.938,-2.35; 67 8.572,2.35; 68 8.572,-2.35; 69 9.207,2.35; 70 9.207,-2.35; 71 9.842,2.35; 72 9.842,-2.35; 73 10.477,2.35; 74 10.477,-2.35; 75 11.113,2.35; 76 11.113,-2.35; 77 11.748,2.35; 78 11.748,-2.35; 79 12.383,2.35; 80 12.383,-2.35
smd 2.5 x 2: M1 -15.45,-0.025; M2 15.45,0
hole 0.9 at -13.635,0
hole 0.7 at 13.635,0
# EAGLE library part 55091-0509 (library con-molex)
0.635 mm PITCH B TO B CONN. Source: http://www.molex.com/pdm_docs/sd/550911609_sd.pdf

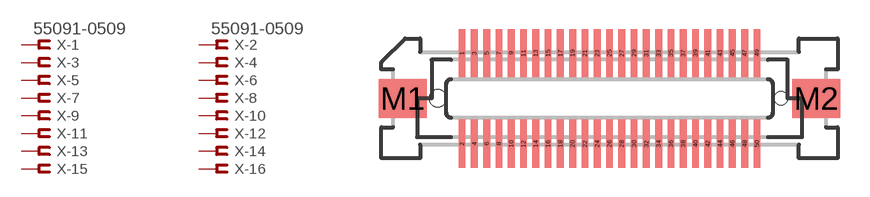
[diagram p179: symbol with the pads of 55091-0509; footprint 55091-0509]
Designator prefix X; gates -1=FV -2=FV -3=F -4=F -5=F -6=F -7=F -8=F -9=F -10=F -11=F -12=F -13=F -14=F -15=F -16=F -17=F -18=F -19=F -20=F -21=F -22=F -23=F -24=F -25=F -26=F -27=F -28=F -29=F -30=F -31=F -32=F -33=F -34=F -35=F -36=F -37=F -38=F -39=F -40=F -41=F -42=F -43=F -44=F -45=F -46=F -47=F -48=F -49=F -50=F

## 55091-0509 (OC_FARNELL: unknown; OC_NEWARK: unknown)  [55091-0509]
1  -1:S  pas
2  -2:S  pas
3  -3:S  pas
4  -4:S  pas
5  -5:S  pas
6  -6:S  pas
7  -7:S  pas
8  -8:S  pas
9  -9:S  pas
10  -10:S  pas
11  -11:S  pas
12  -12:S  pas
13  -13:S  pas
14  -14:S  pas
15  -15:S  pas
16  -16:S  pas
17  -17:S  pas
18  -18:S  pas
19  -19:S  pas
20  -20:S  pas
21  -21:S  pas
22  -22:S  pas
23  -23:S  pas
24  -24:S  pas
25  -25:S  pas
26  -26:S  pas
27  -27:S  pas
28  -28:S  pas
29  -29:S  pas
30  -30:S  pas
31  -31:S  pas
32  -32:S  pas
33  -33:S  pas
34  -34:S  pas
35  -35:S  pas
36  -36:S  pas
37  -37:S  pas
38  -38:S  pas
39  -39:S  pas
40  -40:S  pas
41  -41:S  pas
42  -42:S  pas
43  -43:S  pas
44  -44:S  pas
45  -45:S  pas
46  -46:S  pas
47  -47:S  pas
48  -48:S  pas
49  -49:S  pas
50  -50:S  pas

## Footprint 55091-0509 (pad centres in mm)
0.635 mm PITCH B TO B CONN. Source: http://www.molex.com/pdm_docs/sd/550911609_sd.pdf
smd 0.35 x 2.5: 1 -7.62,2.35; 2 -7.62,-2.35; 3 -6.985,2.35; 4 -6.985,-2.35; 5 -6.35,2.35; 6 -6.35,-2.35; 7 -5.715,2.35; 8 -5.715,-2.35; 9 -5.08,2.35; 10 -5.08,-2.35; 11 -4.445,2.35; 12 -4.445,-2.35; 13 -3.81,2.35; 14 -3.81,-2.35; 15 -3.175,2.35; 16 -3.175,-2.35; 17 -2.54,2.35; 18 -2.54,-2.35; 19 -1.905,2.35; 20 -1.905,-2.35; 21 -1.27,2.35; 22 -1.27,-2.35; 23 -0.635,2.35; 24 -0.635,-2.35; 25 0,2.35; 26 0,-2.35; 27 0.635,2.35; 28 0.635,-2.35; 29 1.27,2.35; 30 1.27,-2.35; 31 1.905,2.35; 32 1.905,-2.35; 33 2.54,2.35; 34 2.54,-2.35; 35 3.175,2.35; 36 3.175,-2.35; 37 3.81,2.35; 38 3.81,-2.35; 39 4.445,2.35; 40 4.445,-2.35; 41 5.08,2.35; 42 5.08,-2.35; 43 5.715,2.35; 44 5.715,-2.35; 45 6.35,2.35; 46 6.35,-2.35; 47 6.985,2.35; 48 6.985,-2.35; 49 7.62,2.35; 50 7.62,-2.35
smd 2.5 x 2: M1 -10.688,0; M2 10.688,0
hole 0.9 at -8.875,0
hole 0.7 at 8.875,0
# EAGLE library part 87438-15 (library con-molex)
Wire-to-Board 1.50mm (.059") Pitch Header - Right Angle, SMT, Shrouded Source: http://www.molex.com/product/micro/87438.html

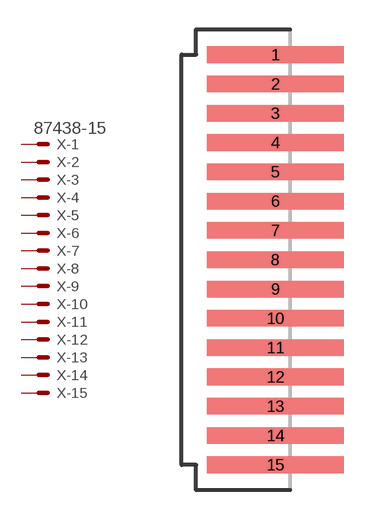
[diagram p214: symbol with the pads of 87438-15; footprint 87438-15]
Designator prefix X; gates -1=MV -2=M -3=M -4=M -5=M -6=M -7=M -8=M -9=M -10=M -11=M -12=M -13=M -14=M -15=M

## 87438-15 (MPN: 87438-1542; OC_FARNELL: unknown; OC_NEWARK: 68K1704)  [87438-15]
1  -1:S  pas
2  -2:S  pas
3  -3:S  pas
4  -4:S  pas
5  -5:S  pas
6  -6:S  pas
7  -7:S  pas
8  -8:S  pas
9  -9:S  pas
10  -10:S  pas
11  -11:S  pas
12  -12:S  pas
13  -13:S  pas
14  -14:S  pas
15  -15:S  pas

## Footprint 87438-15 (pad centres in mm)
Wire-to-Board 1.50mm (.059") Pitch Header - Right Angle, SMT, Shrouded Source: http://www.molex.com/product/micro/87438.html
smd 7 x 0.85: 1 0,10.5; 2 0,9; 3 0,7.5; 4 0,6; 5 0,4.5; 6 0,3; 7 0,1.5; 8 0,0; 9 0,-1.5; 10 0,-3; 11 0,-4.5; 12 0,-6; 13 0,-7.5; 14 0,-9; 15 0,-10.5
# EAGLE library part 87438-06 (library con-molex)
Wire-to-Board 1.50mm (.059") Pitch Header - Right Angle, SMT, Shrouded Source: http://www.molex.com/product/micro/87438.html

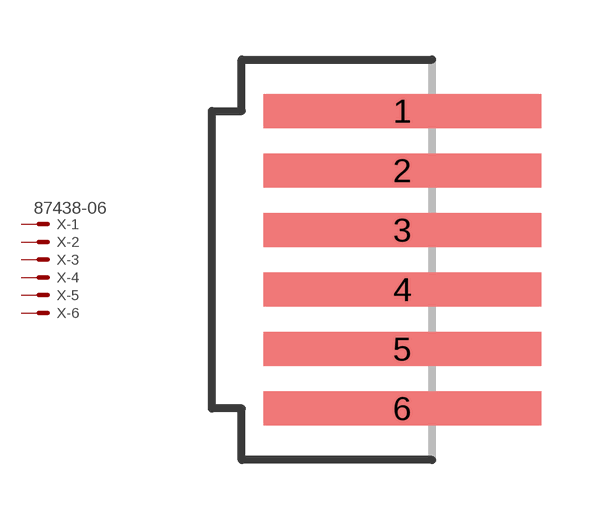
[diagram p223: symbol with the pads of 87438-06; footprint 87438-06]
Designator prefix X; gates -1=MV -2=M -3=M -4=M -5=M -6=M

## 87438-06 (MPN: 87438-0643; OC_FARNELL: 1756938; OC_NEWARK: 88K3155)  [87438-06]
1  -1:S  pas
2  -2:S  pas
3  -3:S  pas
4  -4:S  pas
5  -5:S  pas
6  -6:S  pas

## Footprint 87438-06 (pad centres in mm)
Wire-to-Board 1.50mm (.059") Pitch Header - Right Angle, SMT, Shrouded Source: http://www.molex.com/product/micro/87438.html
smd 7 x 0.85: 1 0,3.75; 2 0,2.25; 3 0,0.75; 4 0,-0.75; 5 0,-2.25; 6 0,-3.75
